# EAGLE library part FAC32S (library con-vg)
CONNECTOR female, 32 pins, block, type D, rows AC, grid 5.08 mm

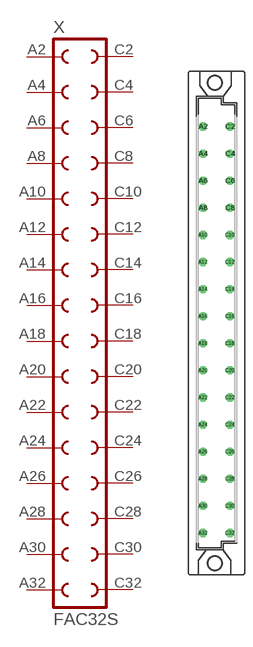
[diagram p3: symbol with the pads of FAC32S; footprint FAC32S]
Designator prefix X

## FAC32S  [FAC32S]
A2  A2  pas
A4  A4  pas
A6  A6  pas
A8  A8  pas
A10  A10  pas
A12  A12  pas
A14  A14  pas
A16  A16  pas
A18  A18  pas
A20  A20  pas
A22  A22  pas
A24  A24  pas
A26  A26  pas
A28  A28  pas
A30  A30  pas
A32  A32  pas
C2  C2  pas
C4  C4  pas
C6  C6  pas
C8  C8  pas
C10  C10  pas
C12  C12  pas
C14  C14  pas
C16  C16  pas
C18  C18  pas
C20  C20  pas
C22  C22  pas
C24  C24  pas
C26  C26  pas
C28  C28  pas
C30  C30  pas
C32  C32  pas

## Footprint FAC32S (pad centres in mm)
CONNECTOR female, 32 pins, type D, rows AC, grid 5.08 mm
drill 1.016 octagon: A2 -2.54,36.83; A4 -2.54,31.75; A6 -2.54,26.67; A8 -2.54,21.59; A10 -2.54,16.51; A12 -2.54,11.43; A14 -2.54,6.35; A16 -2.54,1.27; A18 -2.54,-3.81; A20 -2.54,-8.89; A22 -2.54,-13.97; A24 -2.54,-19.05; A26 -2.54,-24.13; A28 -2.54,-29.21; A30 -2.54,-34.29; A32 -2.54,-39.37; C2 2.54,36.83; C4 2.54,31.75; C6 2.54,26.67; C8 2.54,21.59; C10 2.54,16.51; C12 2.54,11.43; C14 2.54,6.35; C16 2.54,1.27; C18 2.54,-3.81; C20 2.54,-8.89; C22 2.54,-13.97; C24 2.54,-19.05; C26 2.54,-24.13; C28 2.54,-29.21; C30 2.54,-34.29; C32 2.54,-39.37
hole 2.794 at -0.305,45.009
hole 2.794 at -0.305,-45.009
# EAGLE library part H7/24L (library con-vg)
CONNECTOR male, 24 pins + 7 high current pins, block, type H, rows DBZ

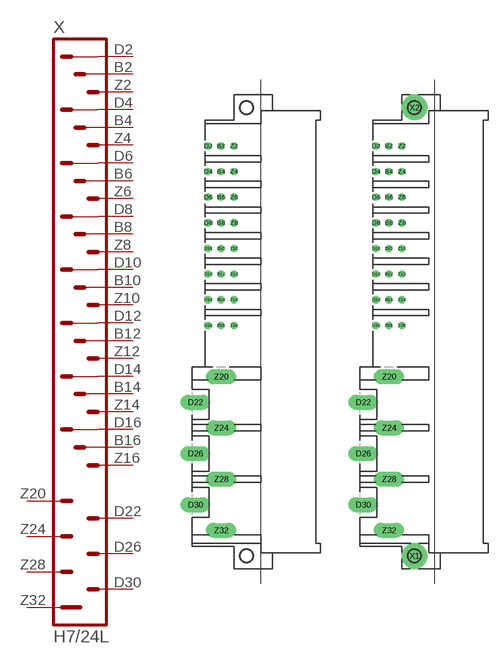
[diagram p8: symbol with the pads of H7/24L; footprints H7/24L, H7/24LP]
Designator prefix X

## H7/24L  [H7/24L]
B2  B2  pas
B4  B4  pas
B6  B6  pas
B8  B8  pas
B10  B10  pas
B12  B12  pas
B14  B14  pas
B16  B16  pas
D2  D2  pas
D4  D4  pas
D6  D6  pas
D8  D8  pas
D10  D10  pas
D12  D12  pas
D14  D14  pas
D16  D16  pas
D22  D22  pas
D26  D26  pas
D30  D30  pas
Z2  Z2  pas
Z4  Z4  pas
Z6  Z6  pas
Z8  Z8  pas
Z10  Z10  pas
Z12  Z12  pas
Z14  Z14  pas
Z16  Z16  pas
Z20  Z20  pas
Z24  Z24  pas
Z28  Z28  pas
Z32  Z32  pas

## H7/24LP  [H7/24LP]
Pads as for H7/24L

## Footprint H7/24L (pad centres in mm)
CONNECTOR male, 24 pins + 7 high current, type H7F24, rows DBZ
drill 0.914 octagon: B2 -5.08,36.83; B4 -5.08,31.75; B6 -5.08,26.67; B8 -5.08,21.59; B10 -5.08,16.51; B12 -5.08,11.43; B14 -5.08,6.35; B16 -5.08,1.27; D2 -7.62,36.83; D4 -7.62,31.75; D6 -7.62,26.67; D8 -7.62,21.59; D10 -7.62,16.51; D12 -7.62,11.43; D14 -7.62,6.35; D16 -7.62,1.27; Z2 -2.54,36.83; Z4 -2.54,31.75; Z6 -2.54,26.67; Z8 -2.54,21.59; Z10 -2.54,16.51; Z12 -2.54,11.43; Z14 -2.54,6.35; Z16 -2.54,1.27
drill 1.6 pad 3 long: D22 -10.16,-13.97; D26 -10.16,-24.13; D30 -10.16,-34.29; Z20 -5.08,-8.89; Z24 -5.08,-19.05; Z28 -5.08,-29.21; Z32 -5.08,-39.37
hole 2.794 at 0,-44.45
hole 2.794 at 0,44.45

## Footprint H7/24LP (pad centres in mm)
CONNECTOR male, 24 pins + 7 high current, type H7F24, rows DBZ with mounting holes
drill 0.914 octagon: B2 -5.08,36.83; B4 -5.08,31.75; B6 -5.08,26.67; B8 -5.08,21.59; B10 -5.08,16.51; B12 -5.08,11.43; B14 -5.08,6.35; B16 -5.08,1.27; D2 -7.62,36.83; D4 -7.62,31.75; D6 -7.62,26.67; D8 -7.62,21.59; D10 -7.62,16.51; D12 -7.62,11.43; D14 -7.62,6.35; D16 -7.62,1.27; Z2 -2.54,36.83; Z4 -2.54,31.75; Z6 -2.54,26.67; Z8 -2.54,21.59; Z10 -2.54,16.51; Z12 -2.54,11.43; Z14 -2.54,6.35; Z16 -2.54,1.27
drill 1.6 pad 3 long: D22 -10.16,-13.97; D26 -10.16,-24.13; D30 -10.16,-34.29; Z20 -5.08,-8.89; Z24 -5.08,-19.05; Z28 -5.08,-29.21; Z32 -5.08,-39.37
drill 2.794 pad 5.08 round: X1 0,-44.45; X2 0,44.45
hole 2.794 at 0,-44.45
hole 2.794 at 0,44.45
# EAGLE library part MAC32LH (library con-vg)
CONNECTOR male, 32 pins, block, type C/2, rows AC, grid 5.08 mm with mounting clip

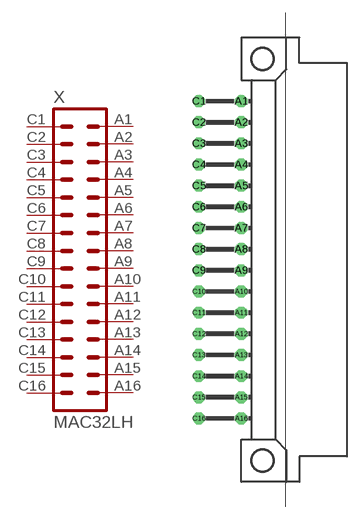
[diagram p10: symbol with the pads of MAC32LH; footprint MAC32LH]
Designator prefix X

## MAC32LH  [MAC32LH]
A1  A1  pas
A2  A2  pas
A3  A3  pas
A4  A4  pas
A5  A5  pas
A6  A6  pas
A7  A7  pas
A8  A8  pas
A9  A9  pas
A10  A10  pas
A11  A11  pas
A12  A12  pas
A13  A13  pas
A14  A14  pas
A15  A15  pas
A16  A16  pas
C1  C1  pas
C2  C2  pas
C3  C3  pas
C4  C4  pas
C5  C5  pas
C6  C6  pas
C7  C7  pas
C8  C8  pas
C9  C9  pas
C10  C10  pas
C11  C11  pas
C12  C12  pas
C13  C13  pas
C14  C14  pas
C15  C15  pas
C16  C16  pas

## Footprint MAC32LH (pad centres in mm)
CONNECTOR male, 32 pins, type C/2, rows AC, grid 5.08 mm with mountig clip
drill 0.914 octagon: A1 -2.54,19.05; A2 -2.54,16.51; A3 -2.54,13.97; A4 -2.54,11.43; A5 -2.54,8.89; A6 -2.54,6.35; A7 -2.54,3.81; A8 -2.54,1.27; A9 -2.54,-1.27; A10 -2.54,-3.81; A11 -2.54,-6.35; A12 -2.54,-8.89; A13 -2.54,-11.43; A14 -2.54,-13.97; A15 -2.54,-16.51; A16 -2.54,-19.05; C1 -7.62,19.05; C2 -7.62,16.51; C3 -7.62,13.97; C4 -7.62,11.43; C5 -7.62,8.89; C6 -7.62,6.35; C7 -7.62,3.81; C8 -7.62,1.27; C9 -7.62,-1.27; C10 -7.62,-3.81; C11 -7.62,-6.35; C12 -7.62,-8.89; C13 -7.62,-11.43; C14 -7.62,-13.97; C15 -7.62,-16.51; C16 -7.62,-19.05
hole 2.794 at 0,-24.13
hole 2.794 at 0,24.13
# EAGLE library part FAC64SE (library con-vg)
CONNECTOR female, 64 pins, single, type C, rows AC, grid 5.08 mm

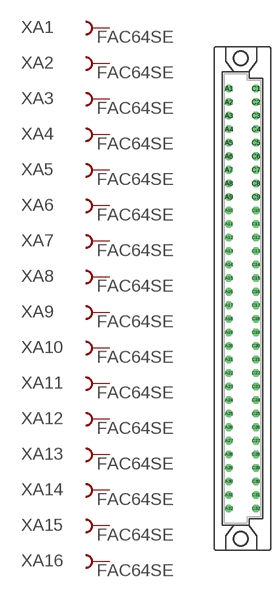
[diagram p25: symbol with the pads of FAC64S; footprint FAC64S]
Designator prefix X; gates A1=F A2=F A3=F A4=F A5=F A6=F A7=F A8=F A9=F A10=F A11=F A12=F A13=F A14=F A15=F A16=F A17=F A18=F A19=F A20=F A21=F A22=F A23=F A24=F A25=F A26=F A27=F A28=F A29=F A30=F A31=F A32=F C1=F C2=F C3=F C4=F C5=F C6=F C7=F C8=F C9=F C10=F C11=F C12=F C13=F C14=F C15=F C16=F C17=F C18=F C19=F C20=F C21=F C22=F C23=F C24=F C25=F C26=F C27=F C28=F C29=F C30=F C31=F C32=F

## FAC64SE  [FAC64S]
A1  A1:B  pas
A2  A2:B  pas
A3  A3:B  pas
A4  A4:B  pas
A5  A5:B  pas
A6  A6:B  pas
A7  A7:B  pas
A8  A8:B  pas
A9  A9:B  pas
A10  A10:B  pas
A11  A11:B  pas
A12  A12:B  pas
A13  A13:B  pas
A14  A14:B  pas
A15  A15:B  pas
A16  A16:B  pas
A17  A17:B  pas
A18  A18:B  pas
A19  A19:B  pas
A20  A20:B  pas
A21  A21:B  pas
A22  A22:B  pas
A23  A23:B  pas
A24  A24:B  pas
A25  A25:B  pas
A26  A26:B  pas
A27  A27:B  pas
A28  A28:B  pas
A29  A29:B  pas
A30  A30:B  pas
A31  A31:B  pas
A32  A32:B  pas
C1  C1:B  pas
C2  C2:B  pas
C3  C3:B  pas
C4  C4:B  pas
C5  C5:B  pas
C6  C6:B  pas
C7  C7:B  pas
C8  C8:B  pas
C9  C9:B  pas
C10  C10:B  pas
C11  C11:B  pas
C12  C12:B  pas
C13  C13:B  pas
C14  C14:B  pas
C15  C15:B  pas
C16  C16:B  pas
C17  C17:B  pas
C18  C18:B  pas
C19  C19:B  pas
C20  C20:B  pas
C21  C21:B  pas
C22  C22:B  pas
C23  C23:B  pas
C24  C24:B  pas
C25  C25:B  pas
C26  C26:B  pas
C27  C27:B  pas
C28  C28:B  pas
C29  C29:B  pas
C30  C30:B  pas
C31  C31:B  pas
C32  C32:B  pas

## Footprint FAC64S (pad centres in mm)
CONNECTOR female, 64 pins, type C, rows AC, grid 5.08 mm
drill 0.914 octagon: A1 -2.54,39.37; A2 -2.54,36.83; A3 -2.54,34.29; A4 -2.54,31.75; A5 -2.54,29.21; A6 -2.54,26.67; A7 -2.54,24.13; A8 -2.54,21.59; A9 -2.54,19.05; A10 -2.54,16.51; A11 -2.54,13.97; A12 -2.54,11.43; A13 -2.54,8.89; A14 -2.54,6.35; A15 -2.54,3.81; A16 -2.54,1.27; A17 -2.54,-1.27; A18 -2.54,-3.81; A19 -2.54,-6.35; A20 -2.54,-8.89; A21 -2.54,-11.43; A22 -2.54,-13.97; A23 -2.54,-16.51; A24 -2.54,-19.05; A25 -2.54,-21.59; A26 -2.54,-24.13; A27 -2.54,-26.67; A28 -2.54,-29.21; A29 -2.54,-31.75; A30 -2.54,-34.29; A31 -2.54,-36.83; A32 -2.54,-39.37; C1 2.54,39.37; C2 2.54,36.83; C3 2.54,34.29; C4 2.54,31.75; C5 2.54,29.21; C6 2.54,26.67; C7 2.54,24.13; C8 2.54,21.59; C9 2.54,19.05; C10 2.54,16.51; C11 2.54,13.97; C12 2.54,11.43; C13 2.54,8.89; C14 2.54,6.35; C15 2.54,3.81; C16 2.54,1.27; C17 2.54,-1.27; C18 2.54,-3.81; C19 2.54,-6.35; C20 2.54,-8.89; C21 2.54,-11.43; C22 2.54,-13.97; C23 2.54,-16.51; C24 2.54,-19.05; C25 2.54,-21.59; C26 2.54,-24.13; C27 2.54,-26.67; C28 2.54,-29.21; C29 2.54,-31.75; C30 2.54,-34.29; C31 2.54,-36.83; C32 2.54,-39.37
hole 2.794 at -0.305,45.009
hole 2.794 at -0.305,-45.009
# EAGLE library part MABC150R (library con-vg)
CONNECTOR male, 150 pins, single, type R, rows ABC, grid 2.54 mm

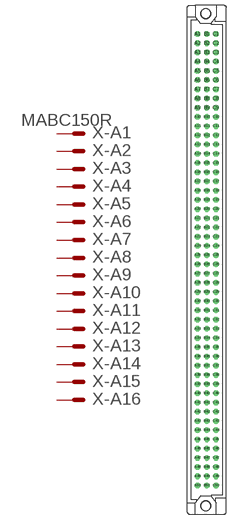
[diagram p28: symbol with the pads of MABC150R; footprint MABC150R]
Designator prefix X; gates -A1=MVAL -A2=MAL -A3=MAL -A4=MAL -A5=MAL -A6=MAL -A7=MAL -A8=MAL -A9=MAL -A10=MAL -A11=MAL -A12=MAL -A13=MAL -A14=MAL -A15=MAL -A16=MAL -A17=MAL -A18=MAL -A19=MAL -A20=MAL -A21=MAL -A22=MAL -A23=MAL -A24=MAL -A25=MAL -A26=MAL -A27=MAL -A28=MAL -A29=MAL -A30=MAL -A31=MAL -A32=MAL -A33=MAL -A34=MAL -A35=MAL -A36=MAL -A37=MAL -A38=MAL -A39=MAL -A40=MAL -A41=MAL -A42=MAL -A43=MAL -A44=MAL -A45=MAL -A46=MAL -A47=MAL -A48=MAL -A49=MAL -A50=MAL -B1=MVAL -B2=MAL -B3=MAL -B4=MAL -B5=MAL -B6=MAL -B7=MAL -B8=MAL -B9=MAL -B10=MAL -B11=MAL -B12=MAL -B13=MAL -B14=MAL -B15=MAL -B16=MAL -B17=MAL -B18=MAL -B19=MAL -B20=MAL -B21=MAL -B22=MAL -B23=MAL -B24=MAL -B25=MAL -B26=MAL -B27=MAL -B28=MAL -B29=MAL -B30=MAL -B31=MAL -B32=MAL -B33=MAL -B34=MAL -B35=MAL -B36=MAL -B37=MAL -B38=MAL -B39=MAL -B40=MAL -B41=MAL -B42=MAL -B43=MAL -B44=MAL -B45=MAL -B46=MAL -B47=MAL -B48=MAL -B49=MAL -B50=MAL -C1=MVAL -C2=MAL -C3=MAL -C4=MAL -C5=MAL -C6=MAL -C7=MAL -C8=MAL -C9=MAL -C10=MAL -C11=MAL -C12=MAL -C13=MAL -C14=MAL -C15=MAL -C16=MAL -C17=MAL -C18=MAL -C19=MAL -C20=MAL -C21=MAL -C22=MAL -C23=MAL -C24=MAL -C25=MAL -C26=MAL -C27=MAL -C28=MAL -C29=MAL -C30=MAL -C31=MAL -C32=MAL -C33=MAL -C34=MAL -C35=MAL -C36=MAL -C37=MAL -C38=MAL -C39=MAL -C40=MAL -C41=MAL -C42=MAL -C43=MAL -C44=MAL -C45=MAL -C46=MAL -C47=MAL -C48=MAL -C49=MAL -C50=MAL

## MABC150R  [MABC150R]
A1  -A1:S  pas
A2  -A2:S  pas
A3  -A3:S  pas
A4  -A4:S  pas
A5  -A5:S  pas
A6  -A6:S  pas
A7  -A7:S  pas
A8  -A8:S  pas
A9  -A9:S  pas
A10  -A10:S  pas
A11  -A11:S  pas
A12  -A12:S  pas
A13  -A13:S  pas
A14  -A14:S  pas
A15  -A15:S  pas
A16  -A16:S  pas
A17  -A17:S  pas
A18  -A18:S  pas
A19  -A19:S  pas
A20  -A20:S  pas
A21  -A21:S  pas
A22  -A22:S  pas
A23  -A23:S  pas
A24  -A24:S  pas
A25  -A25:S  pas
A26  -A26:S  pas
A27  -A27:S  pas
A28  -A28:S  pas
A29  -A29:S  pas
A30  -A30:S  pas
A31  -A31:S  pas
A32  -A32:S  pas
A33  -A33:S  pas
A34  -A34:S  pas
A35  -A35:S  pas
A36  -A36:S  pas
A37  -A37:S  pas
A38  -A38:S  pas
A39  -A39:S  pas
A40  -A40:S  pas
A41  -A41:S  pas
A42  -A42:S  pas
A43  -A43:S  pas
A44  -A44:S  pas
A45  -A45:S  pas
A46  -A46:S  pas
A47  -A47:S  pas
A48  -A48:S  pas
A49  -A49:S  pas
A50  -A50:S  pas
B1  -B1:S  pas
B2  -B2:S  pas
B3  -B3:S  pas
B4  -B4:S  pas
B5  -B5:S  pas
B6  -B6:S  pas
B7  -B7:S  pas
B8  -B8:S  pas
B9  -B9:S  pas
B10  -B10:S  pas
B11  -B11:S  pas
B12  -B12:S  pas
B13  -B13:S  pas
B14  -B14:S  pas
B15  -B15:S  pas
B16  -B16:S  pas
B17  -B17:S  pas
B18  -B18:S  pas
B19  -B19:S  pas
B20  -B20:S  pas
B21  -B21:S  pas
B22  -B22:S  pas
B23  -B23:S  pas
B24  -B24:S  pas
B25  -B25:S  pas
B26  -B26:S  pas
B27  -B27:S  pas
B28  -B28:S  pas
B29  -B29:S  pas
B30  -B30:S  pas
B31  -B31:S  pas
B32  -B32:S  pas
B33  -B33:S  pas
B34  -B34:S  pas
B35  -B35:S  pas
B36  -B36:S  pas
B37  -B37:S  pas
B38  -B38:S  pas
B39  -B39:S  pas
B40  -B40:S  pas
B41  -B41:S  pas
B42  -B42:S  pas
B43  -B43:S  pas
B44  -B44:S  pas
B45  -B45:S  pas
B46  -B46:S  pas
B47  -B47:S  pas
B48  -B48:S  pas
B49  -B49:S  pas
B50  -B50:S  pas
C1  -C1:S  pas
C2  -C2:S  pas
C3  -C3:S  pas
C4  -C4:S  pas
C5  -C5:S  pas
C6  -C6:S  pas
C7  -C7:S  pas
C8  -C8:S  pas
C9  -C9:S  pas
C10  -C10:S  pas
C11  -C11:S  pas
C12  -C12:S  pas
C13  -C13:S  pas
C14  -C14:S  pas
C15  -C15:S  pas
C16  -C16:S  pas
C17  -C17:S  pas
C18  -C18:S  pas
C19  -C19:S  pas
C20  -C20:S  pas
C21  -C21:S  pas
C22  -C22:S  pas
C23  -C23:S  pas
C24  -C24:S  pas
C25  -C25:S  pas
C26  -C26:S  pas
C27  -C27:S  pas
C28  -C28:S  pas
C29  -C29:S  pas
C30  -C30:S  pas
C31  -C31:S  pas
C32  -C32:S  pas
C33  -C33:S  pas
C34  -C34:S  pas
C35  -C35:S  pas
C36  -C36:S  pas
C37  -C37:S  pas
C38  -C38:S  pas
C39  -C39:S  pas
C40  -C40:S  pas
C41  -C41:S  pas
C42  -C42:S  pas
C43  -C43:S  pas
C44  -C44:S  pas
C45  -C45:S  pas
C46  -C46:S  pas
C47  -C47:S  pas
C48  -C48:S  pas
C49  -C49:S  pas
C50  -C50:S  pas

## Footprint MABC150R (pad centres in mm)
CONNECTOR male, 150 pins, type R, rows ABC, grid 2.54 mm
drill 1.016 octagon: A1 -2.54,62.23; A2 -2.54,59.69; A3 -2.54,57.15; A4 -2.54,54.61; A5 -2.54,52.07; A6 -2.54,49.53; A7 -2.54,46.99; A8 -2.54,44.45; A9 -2.54,41.91; A10 -2.54,39.37; A11 -2.54,36.83; A12 -2.54,34.29; A13 -2.54,31.75; A14 -2.54,29.21; A15 -2.54,26.67; A16 -2.54,24.13; A17 -2.54,21.59; A18 -2.54,19.05; A19 -2.54,16.51; A20 -2.54,13.97; A21 -2.54,11.43; A22 -2.54,8.89; A23 -2.54,6.35; A24 -2.54,3.81; A25 -2.54,1.27; A26 -2.54,-1.27; A27 -2.54,-3.81; A28 -2.54,-6.35; A29 -2.54,-8.89; A30 -2.54,-11.43; A31 -2.54,-13.97; A32 -2.54,-16.51; A33 -2.54,-19.05; A34 -2.54,-21.59; A35 -2.54,-24.13; A36 -2.54,-26.67; A37 -2.54,-29.21; A38 -2.54,-31.75; A39 -2.54,-34.29; A40 -2.54,-36.83; A41 -2.54,-39.37; A42 -2.54,-41.91; A43 -2.54,-44.45; A44 -2.54,-46.99; A45 -2.54,-49.53; A46 -2.54,-52.07; A47 -2.54,-54.61; A48 -2.54,-57.15; A49 -2.54,-59.69; A50 -2.54,-62.23; B1 0,62.23; B2 0,59.69; B3 0,57.15; B4 0,54.61; B5 0,52.07; B6 0,49.53; B7 0,46.99; B8 0,44.45; B9 0,41.91; B10 0,39.37; B11 0,36.83; B12 0,34.29; B13 0,31.75; B14 0,29.21; B15 0,26.67; B16 0,24.13; B17 0,21.59; B18 0,19.05; B19 0,16.51; B20 0,13.97; B21 0,11.43; B22 0,8.89; B23 0,6.35; B24 0,3.81; B25 0,1.27; B26 0,-1.27; B27 0,-3.81; B28 0,-6.35; B29 0,-8.89; B30 0,-11.43; B31 0,-13.97; B32 0,-16.51; B33 0,-19.05; B34 0,-21.59; B35 0,-24.13; B36 0,-26.67; B37 0,-29.21; B38 0,-31.75; B39 0,-34.29; B40 0,-36.83; B41 0,-39.37; B42 0,-41.91; B43 0,-44.45; B44 0,-46.99; B45 0,-49.53; B46 0,-52.07; B47 0,-54.61; B48 0,-57.15; B49 0,-59.69; B50 0,-62.23; C1 2.54,62.23; C2 2.54,59.69; C3 2.54,57.15; C4 2.54,54.61; C5 2.54,52.07; C6 2.54,49.53; C7 2.54,46.99; C8 2.54,44.45; C9 2.54,41.91; C10 2.54,39.37; C11 2.54,36.83; C12 2.54,34.29; C13 2.54,31.75; C14 2.54,29.21; C15 2.54,26.67; C16 2.54,24.13; C17 2.54,21.59; C18 2.54,19.05; C19 2.54,16.51; C20 2.54,13.97; C21 2.54,11.43; C22 2.54,8.89; C23 2.54,6.35; C24 2.54,3.81; C25 2.54,1.27; C26 2.54,-1.27; C27 2.54,-3.81; C28 2.54,-6.35; C29 2.54,-8.89; C30 2.54,-11.43; C31 2.54,-13.97; C32 2.54,-16.51; C33 2.54,-19.05; C34 2.54,-21.59; C35 2.54,-24.13; C36 2.54,-26.67; C37 2.54,-29.21; C38 2.54,-31.75; C39 2.54,-34.29; C40 2.54,-36.83; C41 2.54,-39.37; C42 2.54,-41.91; C43 2.54,-44.45; C44 2.54,-46.99; C45 2.54,-49.53; C46 2.54,-52.07; C47 2.54,-54.61; C48 2.54,-57.15; C49 2.54,-59.69; C50 2.54,-62.23
hole 2.794 at -0.305,67.86
hole 2.794 at -0.305,-67.86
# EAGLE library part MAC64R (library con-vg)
CONNECTOR male, 64 pins, single, type R, rows AC, grid 5.08 mm with mounting clip

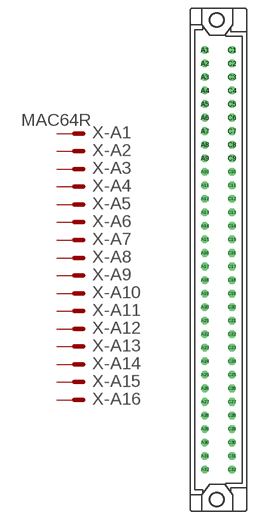
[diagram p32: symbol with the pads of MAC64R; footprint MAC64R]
Designator prefix X; gates -A1=MVAL -A2=MAL -A3=MAL -A4=MAL -A5=MAL -A6=MAL -A7=MAL -A8=MAL -A9=MAL -A10=MAL -A11=MAL -A12=MAL -A13=MAL -A14=MAL -A15=MAL -A16=MAL -A17=MAL -A18=MAL -A19=MAL -A20=MAL -A21=MAL -A22=MAL -A23=MAL -A24=MAL -A25=MAL -A26=MAL -A27=MAL -A28=MAL -A29=MAL -A30=MAL -A31=MAL -A32=MAL -C1=MVAL -C2=MAL -C3=MAL -C4=MAL -C5=MAL -C6=MAL -C7=MAL -C8=MAL -C9=MAL -C10=MAL -C11=MAL -C12=MAL -C13=MAL -C14=MAL -C15=MAL -C16=MAL -C17=MAL -C18=MAL -C19=MAL -C20=MAL -C21=MAL -C22=MAL -C23=MAL -C24=MAL -C25=MAL -C26=MAL -C27=MAL -C28=MAL -C29=MAL -C30=MAL -C31=MAL -C32=MAL

## MAC64R  [MAC64R]
A1  -A1:S  pas
A2  -A2:S  pas
A3  -A3:S  pas
A4  -A4:S  pas
A5  -A5:S  pas
A6  -A6:S  pas
A7  -A7:S  pas
A8  -A8:S  pas
A9  -A9:S  pas
A10  -A10:S  pas
A11  -A11:S  pas
A12  -A12:S  pas
A13  -A13:S  pas
A14  -A14:S  pas
A15  -A15:S  pas
A16  -A16:S  pas
A17  -A17:S  pas
A18  -A18:S  pas
A19  -A19:S  pas
A20  -A20:S  pas
A21  -A21:S  pas
A22  -A22:S  pas
A23  -A23:S  pas
A24  -A24:S  pas
A25  -A25:S  pas
A26  -A26:S  pas
A27  -A27:S  pas
A28  -A28:S  pas
A29  -A29:S  pas
A30  -A30:S  pas
A31  -A31:S  pas
A32  -A32:S  pas
C1  -C1:S  pas
C2  -C2:S  pas
C3  -C3:S  pas
C4  -C4:S  pas
C5  -C5:S  pas
C6  -C6:S  pas
C7  -C7:S  pas
C8  -C8:S  pas
C9  -C9:S  pas
C10  -C10:S  pas
C11  -C11:S  pas
C12  -C12:S  pas
C13  -C13:S  pas
C14  -C14:S  pas
C15  -C15:S  pas
C16  -C16:S  pas
C17  -C17:S  pas
C18  -C18:S  pas
C19  -C19:S  pas
C20  -C20:S  pas
C21  -C21:S  pas
C22  -C22:S  pas
C23  -C23:S  pas
C24  -C24:S  pas
C25  -C25:S  pas
C26  -C26:S  pas
C27  -C27:S  pas
C28  -C28:S  pas
C29  -C29:S  pas
C30  -C30:S  pas
C31  -C31:S  pas
C32  -C32:S  pas

## Footprint MAC64R (pad centres in mm)
CONNECTOR male, 64 pins, type R, rows AC, grid 5.08 mm with mounting clip
drill 0.914 octagon: A1 -2.54,39.37; A2 -2.54,36.83; A3 -2.54,34.29; A4 -2.54,31.75; A5 -2.54,29.21; A6 -2.54,26.67; A7 -2.54,24.13; A8 -2.54,21.59; A9 -2.54,19.05; A10 -2.54,16.51; A11 -2.54,13.97; A12 -2.54,11.43; A13 -2.54,8.89; A14 -2.54,6.35; A15 -2.54,3.81; A16 -2.54,1.27; A17 -2.54,-1.27; A18 -2.54,-3.81; A19 -2.54,-6.35; A20 -2.54,-8.89; A21 -2.54,-11.43; A22 -2.54,-13.97; A23 -2.54,-16.51; A24 -2.54,-19.05; A25 -2.54,-21.59; A26 -2.54,-24.13; A27 -2.54,-26.67; A28 -2.54,-29.21; A29 -2.54,-31.75; A30 -2.54,-34.29; A31 -2.54,-36.83; A32 -2.54,-39.37; C1 2.54,39.37; C2 2.54,36.83; C3 2.54,34.29; C4 2.54,31.75; C5 2.54,29.21; C6 2.54,26.67; C7 2.54,24.13; C8 2.54,21.59; C9 2.54,19.05; C10 2.54,16.51; C11 2.54,13.97; C12 2.54,11.43; C13 2.54,8.89; C14 2.54,6.35; C15 2.54,3.81; C16 2.54,1.27; C17 2.54,-1.27; C18 2.54,-3.81; C19 2.54,-6.35; C20 2.54,-8.89; C21 2.54,-11.43; C22 2.54,-13.97; C23 2.54,-16.51; C24 2.54,-19.05; C25 2.54,-21.59; C26 2.54,-24.13; C27 2.54,-26.67; C28 2.54,-29.21; C29 2.54,-31.75; C30 2.54,-34.29; C31 2.54,-36.83; C32 2.54,-39.37
hole 2.794 at -0.305,45
hole 2.794 at -0.305,-45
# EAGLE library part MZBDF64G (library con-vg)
CONNECTOR male, 64 pins, single, type G, rows DBZ, grid 3.81

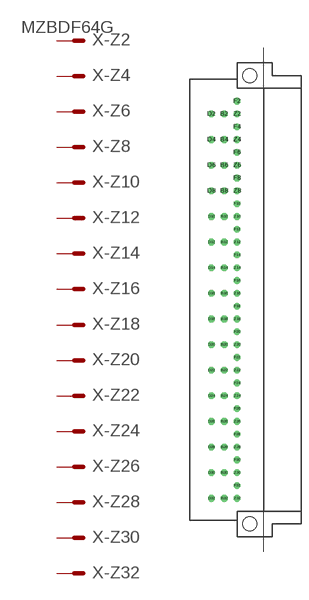
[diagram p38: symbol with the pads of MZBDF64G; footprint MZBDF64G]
Designator prefix X; gates -Z2=MVAL -Z4=MAL -Z6=MAL -Z8=MAL -Z10=MAL -Z12=MAL -Z14=MAL -Z16=MAL -Z18=MAL -Z20=MAL -Z22=MAL -Z24=MAL -Z26=MAL -Z28=MAL -Z30=MAL -Z32=MAL -B2=MVAL -B4=MAL -B6=MAL -B8=MAL -B10=MAL -B12=MAL -B14=MAL -B16=MAL -B18=MAL -B20=MAL -B22=MAL -B24=MAL -B26=MAL -B28=MAL -B30=MAL -B32=MAL -D2=MVAL -D4=MAL -D6=MAL -D8=MAL -D10=MAL -D12=MAL -D14=MAL -D16=MAL -D18=MAL -D20=MAL -D22=MAL -D24=MAL -D26=MAL -D28=MAL -D30=MAL -D32=MAL -F2=MVAL -F4=MAL -F6=MAL -F8=MAL -F10=MAL -F12=MAL -F14=MAL -F16=MAL -F18=MAL -F20=MAL -F22=MAL -F24=MAL -F26=MAL -F28=MAL -F30=MAL -F32=MAL

## MZBDF64G  [MZBDF64G]
B2  -B2:S  pas
B4  -B4:S  pas
B6  -B6:S  pas
B8  -B8:S  pas
B10  -B10:S  pas
B12  -B12:S  pas
B14  -B14:S  pas
B16  -B16:S  pas
B18  -B18:S  pas
B20  -B20:S  pas
B22  -B22:S  pas
B24  -B24:S  pas
B26  -B26:S  pas
B28  -B28:S  pas
B30  -B30:S  pas
B32  -B32:S  pas
D2  -D2:S  pas
D4  -D4:S  pas
D6  -D6:S  pas
D8  -D8:S  pas
D10  -D10:S  pas
D12  -D12:S  pas
D14  -D14:S  pas
D16  -D16:S  pas
D18  -D18:S  pas
D20  -D20:S  pas
D22  -D22:S  pas
D24  -D24:S  pas
D26  -D26:S  pas
D28  -D28:S  pas
D30  -D30:S  pas
D32  -D32:S  pas
F2  -F2:S  pas
F4  -F4:S  pas
F6  -F6:S  pas
F8  -F8:S  pas
F10  -F10:S  pas
F12  -F12:S  pas
F14  -F14:S  pas
F16  -F16:S  pas
F18  -F18:S  pas
F20  -F20:S  pas
F22  -F22:S  pas
F24  -F24:S  pas
F26  -F26:S  pas
F28  -F28:S  pas
F30  -F30:S  pas
F32  -F32:S  pas
Z2  -Z2:S  pas
Z4  -Z4:S  pas
Z6  -Z6:S  pas
Z8  -Z8:S  pas
Z10  -Z10:S  pas
Z12  -Z12:S  pas
Z14  -Z14:S  pas
Z16  -Z16:S  pas
Z18  -Z18:S  pas
Z20  -Z20:S  pas
Z22  -Z22:S  pas
Z24  -Z24:S  pas
Z26  -Z26:S  pas
Z28  -Z28:S  pas
Z30  -Z30:S  pas
Z32  -Z32:S  pas

## Footprint MZBDF64G (pad centres in mm)
CONNECTOR male, 64 pins, type G, rows DBZ, grid 2.54
drill 0.813 octagon: B2 -5.08,36.83; B4 -5.08,31.75; B6 -5.08,26.67; B8 -5.08,21.59; B10 -5.08,16.51; B12 -5.08,11.43; B14 -5.08,6.35; B16 -5.08,1.27; B18 -5.08,-3.81; B20 -5.08,-8.89; B22 -5.08,-13.97; B24 -5.08,-19.05; B26 -5.08,-24.13; B28 -5.08,-29.21; B30 -5.08,-34.29; B32 -5.08,-39.37; D2 -7.62,36.83; D4 -7.62,31.75; D6 -7.62,26.67; D8 -7.62,21.59; D10 -7.62,16.51; D12 -7.62,11.43; D14 -7.62,6.35; D16 -7.62,1.27; D18 -7.62,-3.81; D20 -7.62,-8.89; D22 -7.62,-13.97; D24 -7.62,-19.05; D26 -7.62,-24.13; D28 -7.62,-29.21; D30 -7.62,-34.29; D32 -7.62,-39.37; F2 -2.54,39.37; F4 -2.54,34.29; F6 -2.54,29.21; F8 -2.54,24.13; F10 -2.54,19.05; F12 -2.54,13.97; F14 -2.54,8.89; F16 -2.54,3.81; F18 -2.54,-1.27; F20 -2.54,-6.35; F22 -2.54,-11.43; F24 -2.54,-16.51; F26 -2.54,-21.59; F28 -2.54,-26.67; F30 -2.54,-31.75; F32 -2.54,-36.83; Z2 -2.54,36.83; Z4 -2.54,31.75; Z6 -2.54,26.67; Z8 -2.54,21.59; Z10 -2.54,16.51; Z12 -2.54,11.43; Z14 -2.54,6.35; Z16 -2.54,1.27; Z18 -2.54,-3.81; Z20 -2.54,-8.89; Z22 -2.54,-13.97; Z24 -2.54,-19.05; Z26 -2.54,-24.13; Z28 -2.54,-29.21; Z30 -2.54,-34.29; Z32 -2.54,-39.37
hole 2.794 at 0,44.45
hole 2.794 at 0,-44.45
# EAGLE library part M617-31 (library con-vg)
CONNECTOR male, 31 pins, single, DIN41617

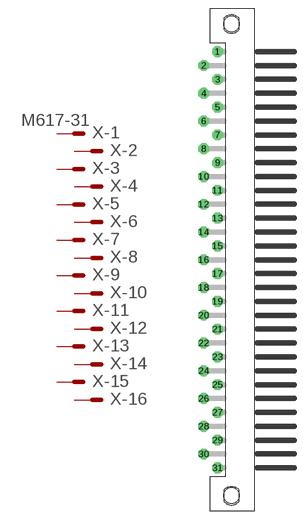
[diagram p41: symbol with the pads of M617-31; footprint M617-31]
Designator prefix X; gates -1=MVAL -2=MAL -3=MAL -4=MAL -5=MAL -6=MAL -7=MAL -8=MAL -9=MAL -10=MAL -11=MAL -12=MAL -13=MAL -14=MAL -15=MAL -16=MAL -17=MAL -18=MAL -19=MAL -20=MAL -21=MAL -22=MAL -23=MAL -24=MAL -25=MAL -26=MAL -27=MAL -28=MAL -29=MAL -30=MAL -31=MAL

## M617-31  [M617-31]
1  -1:S  pas
2  -2:S  pas
3  -3:S  pas
4  -4:S  pas
5  -5:S  pas
6  -6:S  pas
7  -7:S  pas
8  -8:S  pas
9  -9:S  pas
10  -10:S  pas
11  -11:S  pas
12  -12:S  pas
13  -13:S  pas
14  -14:S  pas
15  -15:S  pas
16  -16:S  pas
17  -17:S  pas
18  -18:S  pas
19  -19:S  pas
20  -20:S  pas
21  -21:S  pas
22  -22:S  pas
23  -23:S  pas
24  -24:S  pas
25  -25:S  pas
26  -26:S  pas
27  -27:S  pas
28  -28:S  pas
29  -29:S  pas
30  -30:S  pas
31  -31:S  pas

## Footprint M617-31 (pad centres in mm)
CONNECTOR male, 31 pins, DIN41617
drill 1.3 octagon: 1 -4,35; 2 -6.5,32.5; 3 -4,30; 4 -6.5,27.5; 5 -4,25; 6 -6.5,22.5; 7 -4,20; 8 -6.5,17.5; 9 -4,15; 10 -6.5,12.5; 11 -4,10; 12 -6.5,7.5; 13 -4,5; 14 -6.5,2.5; 15 -4,0; 16 -6.5,-2.5; 17 -4,-5; 18 -6.5,-7.5; 19 -4,-10; 20 -6.5,-12.5; 21 -4,-15; 22 -6.5,-17.5; 23 -4,-20; 24 -6.5,-22.5; 25 -4,-25; 26 -6.5,-27.5; 27 -4,-30; 28 -6.5,-32.5; 29 -4,-35; 30 -6.5,-37.5; 31 -4,-40
hole 2.8 at -1.5,-45
hole 2.8 at -1.5,40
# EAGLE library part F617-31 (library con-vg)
CONNECTOR female, DIN 41617, 31 pins, single

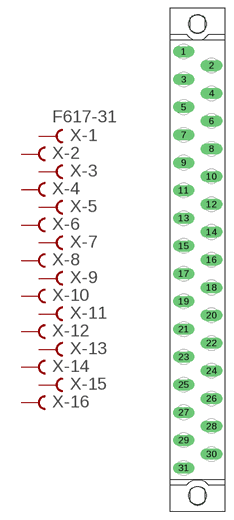
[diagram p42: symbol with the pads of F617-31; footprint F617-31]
Designator prefix X; gates -1=FVAL -2=FEM -3=FEM -4=FEM -5=FEM -6=FEM -7=FEM -8=FEM -9=FEM -10=FEM -11=FEM -12=FEM -13=FEM -14=FEM -15=FEM -16=FEM -17=FEM -18=FEM -19=FEM -20=FEM -21=FEM -22=FEM -23=FEM -24=FEM -25=FEM -26=FEM -27=FEM -28=FEM -29=FEM -30=FEM -31=FEM

## F617-31  [F617-31]
1  -1:B  pas
2  -2:B  pas
3  -3:B  pas
4  -4:B  pas
5  -5:B  pas
6  -6:B  pas
7  -7:B  pas
8  -8:B  pas
9  -9:B  pas
10  -10:B  pas
11  -11:B  pas
12  -12:B  pas
13  -13:B  pas
14  -14:B  pas
15  -15:B  pas
16  -16:B  pas
17  -17:B  pas
18  -18:B  pas
19  -19:B  pas
20  -20:B  pas
21  -21:B  pas
22  -22:B  pas
23  -23:B  pas
24  -24:B  pas
25  -25:B  pas
26  -26:B  pas
27  -27:B  pas
28  -28:B  pas
29  -29:B  pas
30  -30:B  pas
31  -31:B  pas

## Footprint F617-31 (pad centres in mm)
CONNECTOR female, 31 pins, DIN 41617
drill 1.3 long: 1 -2.5,37.5; 2 2.5,35; 3 -2.5,32.5; 4 2.5,30; 5 -2.5,27.5; 6 2.5,25; 7 -2.5,22.5; 8 2.5,20; 9 -2.5,17.5; 10 2.5,15; 11 -2.5,12.5; 12 2.5,10; 13 -2.5,7.5; 14 2.5,5; 15 -2.5,2.5; 16 2.5,0; 17 -2.5,-2.5; 18 2.5,-5; 19 -2.5,-7.5; 20 2.5,-10; 21 -2.5,-12.5; 22 2.5,-15; 23 -2.5,-17.5; 24 2.5,-20; 25 -2.5,-22.5; 26 2.5,-25; 27 -2.5,-27.5; 28 2.5,-30; 29 -2.5,-32.5; 30 2.5,-35; 31 -2.5,-37.5
hole 3.2 at 0,-42.5
hole 3.2 at 0,42.5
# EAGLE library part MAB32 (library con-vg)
CONNECTOR male, 32 pins, type B, row A, grid 2.54 mm

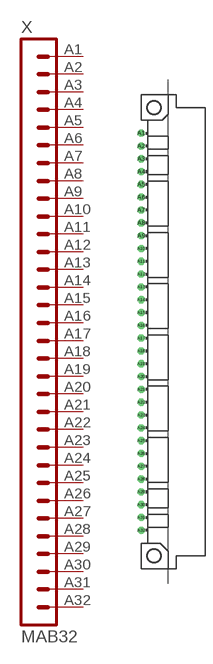
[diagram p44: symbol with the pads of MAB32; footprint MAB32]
Designator prefix X

## MAB32  [MAB32]
A1  1  pas
A2  2  pas
A3  3  pas
A4  4  pas
A5  5  pas
A6  6  pas
A7  7  pas
A8  8  pas
A9  9  pas
A10  10  pas
A11  11  pas
A12  12  pas
A13  13  pas
A14  14  pas
A15  15  pas
A16  16  pas
A17  17  pas
A18  18  pas
A19  19  pas
A20  20  pas
A21  21  pas
A22  22  pas
A23  23  pas
A24  24  pas
A25  25  pas
A26  26  pas
A27  27  pas
A28  28  pas
A29  29  pas
A30  30  pas
A31  31  pas
A32  32  pas

## Footprint MAB32 (pad centres in mm)
CONNECTOR male, 32 pins, type B, rows A, grid 2.54 mm
drill 0.914 octagon: A1 -2.54,39.37; A2 -2.54,36.83; A3 -2.54,34.29; A4 -2.54,31.75; A5 -2.54,29.21; A6 -2.54,26.67; A7 -2.54,24.13; A8 -2.54,21.59; A9 -2.54,19.05; A10 -2.54,16.51; A11 -2.54,13.97; A12 -2.54,11.43; A13 -2.54,8.89; A14 -2.54,6.35; A15 -2.54,3.81; A16 -2.54,1.27; A17 -2.54,-1.27; A18 -2.54,-3.81; A19 -2.54,-6.35; A20 -2.54,-8.89; A21 -2.54,-11.43; A22 -2.54,-13.97; A23 -2.54,-16.51; A24 -2.54,-19.05; A25 -2.54,-21.59; A26 -2.54,-24.13; A27 -2.54,-26.67; A28 -2.54,-29.21; A29 -2.54,-31.75; A30 -2.54,-34.29; A31 -2.54,-36.83; A32 -2.54,-39.37
hole 2.794 at 0,44.45
hole 2.794 at 0,-44.45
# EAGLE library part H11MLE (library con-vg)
CONNECTOR male, 11 high current pins, block, type H

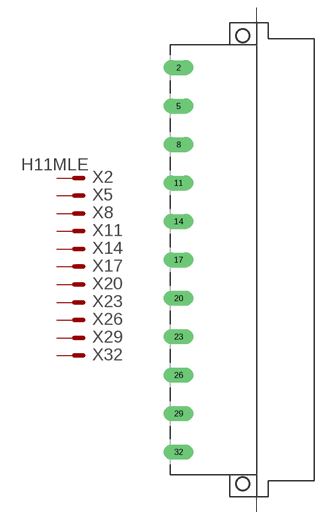
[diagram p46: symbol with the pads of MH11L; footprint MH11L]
Designator prefix X; gates 2=MVAL 5=MAL 8=MAL 11=MAL 14=MAL 17=MAL 20=MAL 23=MAL 26=MAL 29=MAL 32=MAL

## H11MLE  [MH11L]
2  2:S  pas
5  5:S  pas
8  8:S  pas
11  11:S  pas
14  14:S  pas
17  17:S  pas
20  20:S  pas
23  23:S  pas
26  26:S  pas
29  29:S  pas
32  32:S  pas

## Footprint MH11L (pad centres in mm)
CONNECTOR male, 11 pins, type H
drill 1.676 pad 3 long: 2 -12.7,38.1; 5 -12.7,30.48; 8 -12.7,22.86; 11 -12.7,15.24; 14 -12.7,7.62; 17 -12.7,0; 20 -12.7,-7.62; 23 -12.7,-15.24; 26 -12.7,-22.86; 29 -12.7,-30.48; 32 -12.7,-38.1
hole 2.794 at 0,-44.45
hole 2.794 at 0,44.45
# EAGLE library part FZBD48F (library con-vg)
CONNECTOR female, 48 pins, type F, rows ABZ, grid 5.08 mm

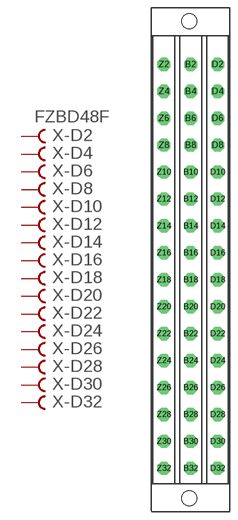
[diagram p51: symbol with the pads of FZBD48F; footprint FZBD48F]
Designator prefix X; gates -D2=FVAL -D4=FEM -D6=FEM -D8=FEM -D10=FEM -D12=FEM -D14=FEM -D16=FEM -D18=FEM -D20=FEM -D22=FEM -D24=FEM -D26=FEM -D28=FEM -D30=FEM -D32=FEM -B2=FVAL -B4=FEM -B6=FEM -B8=FEM -B10=FEM -B12=FEM -B14=FEM -B16=FEM -B18=FEM -B20=FEM -B22=FEM -B24=FEM -B26=FEM -B28=FEM -B30=FEM -B32=FEM -Z2=FVAL -Z4=FEM -Z6=FEM -Z8=FEM -Z10=FEM -Z12=FEM -Z14=FEM -Z16=FEM -Z18=FEM -Z20=FEM -Z22=FEM -Z24=FEM -Z26=FEM -Z28=FEM -Z30=FEM -Z32=FEM

## FZBD48F  [FZBD48F]
B2  -B2:B  pas
B4  -B4:B  pas
B6  -B6:B  pas
B8  -B8:B  pas
B10  -B10:B  pas
B12  -B12:B  pas
B14  -B14:B  pas
B16  -B16:B  pas
B18  -B18:B  pas
B20  -B20:B  pas
B22  -B22:B  pas
B24  -B24:B  pas
B26  -B26:B  pas
B28  -B28:B  pas
B30  -B30:B  pas
B32  -B32:B  pas
D2  -D2:B  pas
D4  -D4:B  pas
D6  -D6:B  pas
D8  -D8:B  pas
D10  -D10:B  pas
D12  -D12:B  pas
D14  -D14:B  pas
D16  -D16:B  pas
D18  -D18:B  pas
D20  -D20:B  pas
D22  -D22:B  pas
D24  -D24:B  pas
D26  -D26:B  pas
D28  -D28:B  pas
D30  -D30:B  pas
D32  -D32:B  pas
Z2  -Z2:B  pas
Z4  -Z4:B  pas
Z6  -Z6:B  pas
Z8  -Z8:B  pas
Z10  -Z10:B  pas
Z12  -Z12:B  pas
Z14  -Z14:B  pas
Z16  -Z16:B  pas
Z18  -Z18:B  pas
Z20  -Z20:B  pas
Z22  -Z22:B  pas
Z24  -Z24:B  pas
Z26  -Z26:B  pas
Z28  -Z28:B  pas
Z30  -Z30:B  pas
Z32  -Z32:B  pas

## Footprint FZBD48F (pad centres in mm)
CONNECTOR female, 48 pins, type F, rows ABZ, grid 5.08 mm
drill 1.676 octagon: B2 0,36.855; B4 0,31.775; B6 0,26.695; B8 0,21.615; B10 0,16.535; B12 0,11.455; B14 0,6.375; B16 0,1.295; B18 0,-3.785; B20 0,-8.865; B22 0,-13.945; B24 0,-19.025; B26 0,-24.105; B28 0,-29.185; B30 0,-34.265; B32 0,-39.345; D2 5.08,36.855; D4 5.08,31.775; D6 5.08,26.695; D8 5.08,21.615; D10 5.08,16.535; D12 5.08,11.455; D14 5.08,6.375; D16 5.08,1.295; D18 5.08,-3.785; D20 5.08,-8.865; D22 5.08,-13.945; D24 5.08,-19.025; D26 5.08,-24.105; D28 5.08,-29.185; D30 5.08,-34.265; D32 5.08,-39.345; Z2 -5.08,36.855; Z4 -5.08,31.775; Z6 -5.08,26.695; Z8 -5.08,21.615; Z10 -5.08,16.535; Z12 -5.08,11.455; Z14 -5.08,6.375; Z16 -5.08,1.295; Z18 -5.08,-3.785; Z20 -5.08,-8.865; Z22 -5.08,-13.945; Z24 -5.08,-19.025; Z26 -5.08,-24.105; Z28 -5.08,-29.185; Z30 -5.08,-34.265; Z32 -5.08,-39.345
hole 2.794 at -0.305,44.983
hole 2.794 at -0.305,-44.983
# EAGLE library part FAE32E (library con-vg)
CONNECTOR femlae 32 pins, type E, rows AC, grid 5.08 mm

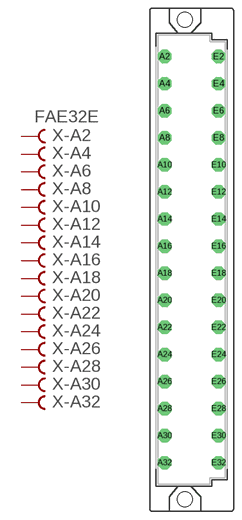
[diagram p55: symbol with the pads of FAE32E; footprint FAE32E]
Designator prefix X; gates -A2=FVAL -A4=FEM -A6=FEM -A8=FEM -A10=FEM -A12=FEM -A14=FEM -A16=FEM -A18=FEM -A20=FEM -A22=FEM -A24=FEM -A26=FEM -A28=FEM -A30=FEM -A32=FEM -E2=FVAL -E4=FEM -E6=FEM -E8=FEM -E10=FEM -E12=FEM -E14=FEM -E16=FEM -E18=FEM -E20=FEM -E22=FEM -E24=FEM -E26=FEM -E28=FEM -E30=FEM -E32=FEM

## FAE32E  [FAE32E]
A2  -A2:B  pas
A4  -A4:B  pas
A6  -A6:B  pas
A8  -A8:B  pas
A10  -A10:B  pas
A12  -A12:B  pas
A14  -A14:B  pas
A16  -A16:B  pas
A18  -A18:B  pas
A20  -A20:B  pas
A22  -A22:B  pas
A24  -A24:B  pas
A26  -A26:B  pas
A28  -A28:B  pas
A30  -A30:B  pas
A32  -A32:B  pas
E2  -E2:B  pas
E4  -E4:B  pas
E6  -E6:B  pas
E8  -E8:B  pas
E10  -E10:B  pas
E12  -E12:B  pas
E14  -E14:B  pas
E16  -E16:B  pas
E18  -E18:B  pas
E20  -E20:B  pas
E22  -E22:B  pas
E24  -E24:B  pas
E26  -E26:B  pas
E28  -E28:B  pas
E30  -E30:B  pas
E32  -E32:B  pas

## Footprint FAE32E (pad centres in mm)
CONNECTOR femlae 32 pins, type E, rows AC, grid 5.08 mm
drill 1.676 octagon: A2 -5.08,38.1; A4 -5.08,33.02; A6 -5.08,27.94; A8 -5.08,22.86; A10 -5.08,17.78; A12 -5.08,12.7; A14 -5.08,7.62; A16 -5.08,2.54; A18 -5.08,-2.54; A20 -5.08,-7.62; A22 -5.08,-12.7; A24 -5.08,-17.78; A26 -5.08,-22.86; A28 -5.08,-27.94; A30 -5.08,-33.02; A32 -5.08,-38.1; E2 5.08,38.1; E4 5.08,33.02; E6 5.08,27.94; E8 5.08,22.86; E10 5.08,17.78; E12 5.08,12.7; E14 5.08,7.62; E16 5.08,2.54; E18 5.08,-2.54; E20 5.08,-7.62; E22 5.08,-12.7; E24 5.08,-17.78; E26 5.08,-22.86; E28 5.08,-27.94; E30 5.08,-33.02; E32 5.08,-38.1
hole 2.794 at -1.27,44.983
hole 2.794 at -1.27,-44.983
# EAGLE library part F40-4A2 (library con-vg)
CONNECTOR female, 40 pins + 4 high current, type C

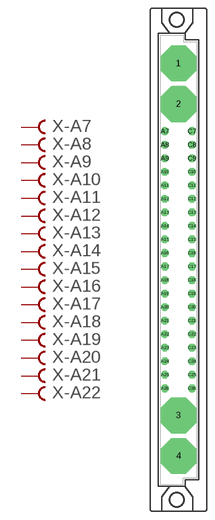
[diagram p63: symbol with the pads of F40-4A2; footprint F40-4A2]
Designator prefix X; gates -A7=FEM -A8=FEM -A9=FEM -A10=FEM -A11=FEM -A12=FEM -A13=FEM -A14=FEM -A15=FEM -A16=FEM -A17=FEM -A18=FEM -A19=FEM -A20=FEM -A21=FEM -A22=FEM -A23=FEM -A24=FEM -A25=FEM -A26=FEM -C7=FEM -C8=FEM -C9=FEM -C10=FEM -C11=FEM -C12=FEM -C13=FEM -C14=FEM -C15=FEM -C16=FEM -C17=FEM -C18=FEM -C19=FEM -C20=FEM -C21=FEM -C22=FEM -C23=FEM -C24=FEM -C25=FEM -C26=FEM -1=FEM-HIGHCUR -2=FEM-HIGHCUR -3=FEM-HIGHCUR -4=FEM-HIGHCUR

## F40-4A2  [F40-4A2]
1  -1:B  pas
2  -2:B  pas
3  -3:B  pas
4  -4:B  pas
A7  -A7:B  pas
A8  -A8:B  pas
A9  -A9:B  pas
A10  -A10:B  pas
A11  -A11:B  pas
A12  -A12:B  pas
A13  -A13:B  pas
A14  -A14:B  pas
A15  -A15:B  pas
A16  -A16:B  pas
A17  -A17:B  pas
A18  -A18:B  pas
A19  -A19:B  pas
A20  -A20:B  pas
A21  -A21:B  pas
A22  -A22:B  pas
A23  -A23:B  pas
A24  -A24:B  pas
A25  -A25:B  pas
A26  -A26:B  pas
C7  -C7:B  pas
C8  -C8:B  pas
C9  -C9:B  pas
C10  -C10:B  pas
C11  -C11:B  pas
C12  -C12:B  pas
C13  -C13:B  pas
C14  -C14:B  pas
C15  -C15:B  pas
C16  -C16:B  pas
C17  -C17:B  pas
C18  -C18:B  pas
C19  -C19:B  pas
C20  -C20:B  pas
C21  -C21:B  pas
C22  -C22:B  pas
C23  -C23:B  pas
C24  -C24:B  pas
C25  -C25:B  pas
C26  -C26:B  pas

## Footprint F40-4A2 (pad centres in mm)
CONNECTOR female, 40 pins + 4 high current, type C
drill 5.7 octagon: 1 0,36.83; 2 0,29.21; 3 0,-29.21; 4 0,-36.83
drill 0.914 octagon: A7 -2.54,24.13; A8 -2.54,21.59; A9 -2.54,19.05; A10 -2.54,16.51; A11 -2.54,13.97; A12 -2.54,11.43; A13 -2.54,8.89; A14 -2.54,6.35; A15 -2.54,3.81; A16 -2.54,1.27; A17 -2.54,-1.27; A18 -2.54,-3.81; A19 -2.54,-6.35; A20 -2.54,-8.89; A21 -2.54,-11.43; A22 -2.54,-13.97; A23 -2.54,-16.51; A24 -2.54,-19.05; A25 -2.54,-21.59; A26 -2.54,-24.13; C7 2.54,24.13; C8 2.54,21.59; C9 2.54,19.05; C10 2.54,16.51; C11 2.54,13.97; C12 2.54,11.43; C13 2.54,8.89; C14 2.54,6.35; C15 2.54,3.81; C16 2.54,1.27; C17 2.54,-1.27; C18 2.54,-3.81; C19 2.54,-6.35; C20 2.54,-8.89; C21 2.54,-11.43; C22 2.54,-13.97; C23 2.54,-16.51; C24 2.54,-19.05; C25 2.54,-21.59; C26 2.54,-24.13
hole 2.794 at -0.305,45.009
hole 2.794 at -0.305,-45.009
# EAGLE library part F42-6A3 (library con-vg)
CONNECTOR female, 42 pins + 6 high current, type C

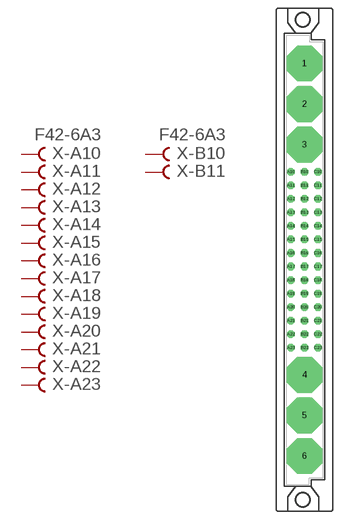
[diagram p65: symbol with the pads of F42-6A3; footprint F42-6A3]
Designator prefix X; gates -A10=FVAL -A11=FEM -A12=FEM -A13=FEM -A14=FEM -A15=FEM -A16=FEM -A17=FEM -A18=FEM -A19=FEM -A20=FEM -A21=FEM -A22=FEM -A23=FEM -B10=FVAL -B11=FEM -B12=FEM -B13=FEM -B14=FEM -B15=FEM -B16=FEM -B17=FEM -B18=FEM -B19=FEM -B20=FEM -B21=FEM -B22=FEM -B23=FEM -C10=FVAL -C11=FEM -C12=FEM -C13=FEM -C14=FEM -C15=FEM -C16=FEM -C17=FEM -C18=FEM -C19=FEM -C20=FEM -C21=FEM -C22=FEM -C23=FEM -1=FEM-HIGHCUR -2=FEM-HIGHCUR -3=FEM-HIGHCUR -4=FEM-HIGHCUR -5=FEM-HIGHCUR -6=FEM-HIGHCUR

## F42-6A3  [F42-6A3]
1  -1:B  pas
2  -2:B  pas
3  -3:B  pas
4  -4:B  pas
5  -5:B  pas
6  -6:B  pas
A10  -A10:B  pas
A11  -A11:B  pas
A12  -A12:B  pas
A13  -A13:B  pas
A14  -A14:B  pas
A15  -A15:B  pas
A16  -A16:B  pas
A17  -A17:B  pas
A18  -A18:B  pas
A19  -A19:B  pas
A20  -A20:B  pas
A21  -A21:B  pas
A22  -A22:B  pas
A23  -A23:B  pas
B10  -B10:B  pas
B11  -B11:B  pas
B12  -B12:B  pas
B13  -B13:B  pas
B14  -B14:B  pas
B15  -B15:B  pas
B16  -B16:B  pas
B17  -B17:B  pas
B18  -B18:B  pas
B19  -B19:B  pas
B20  -B20:B  pas
B21  -B21:B  pas
B22  -B22:B  pas
B23  -B23:B  pas
C10  -C10:B  pas
C11  -C11:B  pas
C12  -C12:B  pas
C13  -C13:B  pas
C14  -C14:B  pas
C15  -C15:B  pas
C16  -C16:B  pas
C17  -C17:B  pas
C18  -C18:B  pas
C19  -C19:B  pas
C20  -C20:B  pas
C21  -C21:B  pas
C22  -C22:B  pas
C23  -C23:B  pas

## Footprint F42-6A3 (pad centres in mm)
CONNECTOR female, 42 pins + 6 high current, type C
drill 5.7 octagon: 1 0,36.83; 2 0,29.21; 3 0,21.59; 4 0,-21.59; 5 0,-29.21; 6 0,-36.83
drill 0.914 octagon: A10 -2.54,16.51; A11 -2.54,13.97; A12 -2.54,11.43; A13 -2.54,8.89; A14 -2.54,6.35; A15 -2.54,3.81; A16 -2.54,1.27; A17 -2.54,-1.27; A18 -2.54,-3.81; A19 -2.54,-6.35; A20 -2.54,-8.89; A21 -2.54,-11.43; A22 -2.54,-13.97; A23 -2.54,-16.51; B10 0,16.51; B11 0,13.97; B12 0,11.43; B13 0,8.89; B14 0,6.35; B15 0,3.81; B16 0,1.27; B17 0,-1.27; B18 0,-3.81; B19 0,-6.35; B20 0,-8.89; B21 0,-11.43; B22 0,-13.97; B23 0,-16.51; C10 2.54,16.51; C11 2.54,13.97; C12 2.54,11.43; C13 2.54,8.89; C14 2.54,6.35; C15 2.54,3.81; C16 2.54,1.27; C17 2.54,-1.27; C18 2.54,-3.81; C19 2.54,-6.35; C20 2.54,-8.89; C21 2.54,-11.43; C22 2.54,-13.97; C23 2.54,-16.51
hole 2.794 at -0.305,45.009
hole 2.794 at -0.305,-45.009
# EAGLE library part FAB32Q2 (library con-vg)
CONNECTOR female, 32 pins, type Q/2, rows AB, grid 2.54 mm

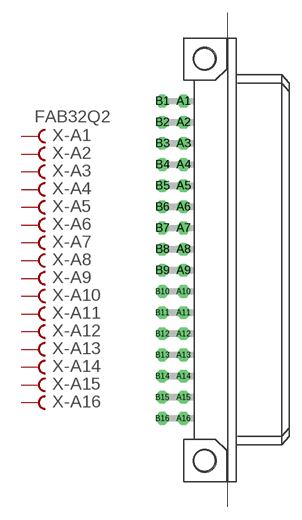
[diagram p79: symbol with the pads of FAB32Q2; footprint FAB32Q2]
Designator prefix X; gates -A1=FVAL -A2=FEM -A3=FEM -A4=FEM -A5=FEM -A6=FEM -A7=FEM -A8=FEM -A9=FEM -A10=FEM -A11=FEM -A12=FEM -A13=FEM -A14=FEM -A15=FEM -A16=FEM -B1=FVAL -B2=FEM -B3=FEM -B4=FEM -B5=FEM -B6=FEM -B7=FEM -B8=FEM -B9=FEM -B10=FEM -B11=FEM -B12=FEM -B13=FEM -B14=FEM -B15=FEM -B16=FEM

## FAB32Q2  [FAB32Q2]
A1  -A1:B  pas
A2  -A2:B  pas
A3  -A3:B  pas
A4  -A4:B  pas
A5  -A5:B  pas
A6  -A6:B  pas
A7  -A7:B  pas
A8  -A8:B  pas
A9  -A9:B  pas
A10  -A10:B  pas
A11  -A11:B  pas
A12  -A12:B  pas
A13  -A13:B  pas
A14  -A14:B  pas
A15  -A15:B  pas
A16  -A16:B  pas
B1  -B1:B  pas
B2  -B2:B  pas
B3  -B3:B  pas
B4  -B4:B  pas
B5  -B5:B  pas
B6  -B6:B  pas
B7  -B7:B  pas
B8  -B8:B  pas
B9  -B9:B  pas
B10  -B10:B  pas
B11  -B11:B  pas
B12  -B12:B  pas
B13  -B13:B  pas
B14  -B14:B  pas
B15  -B15:B  pas
B16  -B16:B  pas

## Footprint FAB32Q2 (pad centres in mm)
CONNECTOR female, 32 pins, type Q/2, rows AB, grid 2.54 mm
drill 1.016 octagon: A1 -2.54,19.05; A2 -2.54,16.51; A3 -2.54,13.97; A4 -2.54,11.43; A5 -2.54,8.89; A6 -2.54,6.35; A7 -2.54,3.81; A8 -2.54,1.27; A9 -2.54,-1.27; A10 -2.54,-3.81; A11 -2.54,-6.35; A12 -2.54,-8.89; A13 -2.54,-11.43; A14 -2.54,-13.97; A15 -2.54,-16.51; A16 -2.54,-19.05; B1 -5.08,19.05; B2 -5.08,16.51; B3 -5.08,13.97; B4 -5.08,11.43; B5 -5.08,8.89; B6 -5.08,6.35; B7 -5.08,3.81; B8 -5.08,1.27; B9 -5.08,-1.27; B10 -5.08,-3.81; B11 -5.08,-6.35; B12 -5.08,-8.89; B13 -5.08,-11.43; B14 -5.08,-13.97; B15 -5.08,-16.51; B16 -5.08,-19.05
hole 2.794 at 0,-24.136
hole 2.794 at 0,24.136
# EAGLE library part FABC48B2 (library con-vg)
CONNECTOR female, 48 pins, type C/2, rows ABC, grid 2.54 mm

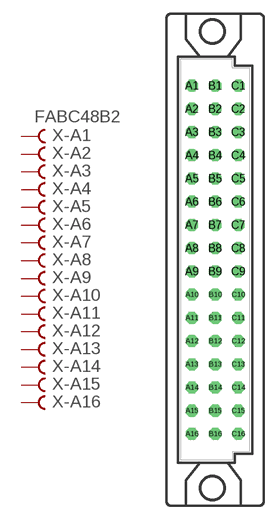
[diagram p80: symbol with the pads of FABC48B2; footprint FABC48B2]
Designator prefix X; gates -A1=FVAL -A2=FEM -A3=FEM -A4=FEM -A5=FEM -A6=FEM -A7=FEM -A8=FEM -A9=FEM -A10=FEM -A11=FEM -A12=FEM -A13=FEM -A14=FEM -A15=FEM -A16=FEM -B1=FVAL -B2=FEM -B3=FEM -B4=FEM -B5=FEM -B6=FEM -B7=FEM -B8=FEM -B9=FEM -B10=FEM -B11=FEM -B12=FEM -B13=FEM -B14=FEM -B15=FEM -B16=FEM -C1=FVAL -C2=FEM -C3=FEM -C4=FEM -C5=FEM -C6=FEM -C7=FEM -C8=FEM -C9=FEM -C10=FEM -C11=FEM -C12=FEM -C13=FEM -C14=FEM -C15=FEM -C16=FEM

## FABC48B2  [FABC48B2]
A1  -A1:B  pas
A2  -A2:B  pas
A3  -A3:B  pas
A4  -A4:B  pas
A5  -A5:B  pas
A6  -A6:B  pas
A7  -A7:B  pas
A8  -A8:B  pas
A9  -A9:B  pas
A10  -A10:B  pas
A11  -A11:B  pas
A12  -A12:B  pas
A13  -A13:B  pas
A14  -A14:B  pas
A15  -A15:B  pas
A16  -A16:B  pas
B1  -B1:B  pas
B2  -B2:B  pas
B3  -B3:B  pas
B4  -B4:B  pas
B5  -B5:B  pas
B6  -B6:B  pas
B7  -B7:B  pas
B8  -B8:B  pas
B9  -B9:B  pas
B10  -B10:B  pas
B11  -B11:B  pas
B12  -B12:B  pas
B13  -B13:B  pas
B14  -B14:B  pas
B15  -B15:B  pas
B16  -B16:B  pas
C1  -C1:B  pas
C2  -C2:B  pas
C3  -C3:B  pas
C4  -C4:B  pas
C5  -C5:B  pas
C6  -C6:B  pas
C7  -C7:B  pas
C8  -C8:B  pas
C9  -C9:B  pas
C10  -C10:B  pas
C11  -C11:B  pas
C12  -C12:B  pas
C13  -C13:B  pas
C14  -C14:B  pas
C15  -C15:B  pas
C16  -C16:B  pas

## Footprint FABC48B2 (pad centres in mm)
CONNECTOR female, 48 pins, type C/2, rows ABC, grid 2.54 mm
drill 0.813 octagon: A1 -1.27,19.05; A2 -1.27,16.51; A3 -1.27,13.97; A4 -1.27,11.43; A5 -1.27,8.89; A6 -1.27,6.35; A7 -1.27,3.81; A8 -1.27,1.27; A9 -1.27,-1.27; A10 -1.27,-3.81; A11 -1.27,-6.35; A12 -1.27,-8.89; A13 -1.27,-11.43; A14 -1.27,-13.97; A15 -1.27,-16.51; A16 -1.27,-19.05; B1 1.27,19.05; B2 1.27,16.51; B3 1.27,13.97; B4 1.27,11.43; B5 1.27,8.89; B6 1.27,6.35; B7 1.27,3.81; B8 1.27,1.27; B9 1.27,-1.27; B10 1.27,-3.81; B11 1.27,-6.35; B12 1.27,-8.89; B13 1.27,-11.43; B14 1.27,-13.97; B15 1.27,-16.51; B16 1.27,-19.05; C1 3.81,19.05; C2 3.81,16.51; C3 3.81,13.97; C4 3.81,11.43; C5 3.81,8.89; C6 3.81,6.35; C7 3.81,3.81; C8 3.81,1.27; C9 3.81,-1.27; C10 3.81,-3.81; C11 3.81,-6.35; C12 3.81,-8.89; C13 3.81,-11.43; C14 3.81,-13.97; C15 3.81,-16.51; C16 3.81,-19.05
hole 2.794 at 0.965,-25
hole 2.794 at 0.965,25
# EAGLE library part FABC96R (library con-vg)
CONNECTOR female, 96 pins, type R, rows ABC, grid 2.54 mm

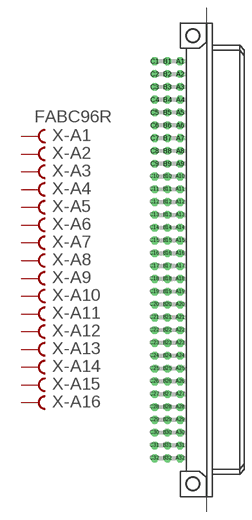
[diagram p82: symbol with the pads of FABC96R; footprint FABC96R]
Designator prefix X; gates -A1=FVAL -A2=FEM -A3=FEM -A4=FEM -A5=FEM -A6=FEM -A7=FEM -A8=FEM -A9=FEM -A10=FEM -A11=FEM -A12=FEM -A13=FEM -A14=FEM -A15=FEM -A16=FEM -A17=FEM -A18=FEM -A19=FEM -A20=FEM -A21=FEM -A22=FEM -A23=FEM -A24=FEM -A25=FEM -A26=FEM -A27=FEM -A28=FEM -A29=FEM -A30=FEM -A31=FEM -A32=FEM -B1=FVAL -B2=FEM -B3=FEM -B4=FEM -B5=FEM -B6=FEM -B7=FEM -B8=FEM -B9=FEM -B10=FEM -B11=FEM -B12=FEM -B13=FEM -B14=FEM -B15=FEM -B16=FEM -B17=FEM -B18=FEM -B19=FEM -B20=FEM -B21=FEM -B22=FEM -B23=FEM -B24=FEM -B25=FEM -B26=FEM -B27=FEM -B28=FEM -B29=FEM -B30=FEM -B31=FEM -B32=FEM -C1=FVAL -C2=FEM -C3=FEM -C4=FEM -C5=FEM -C6=FEM -C7=FEM -C8=FEM -C9=FEM -C10=FEM -C11=FEM -C12=FEM -C13=FEM -C14=FEM -C15=FEM -C16=FEM -C17=FEM -C18=FEM -C19=FEM -C20=FEM -C21=FEM -C22=FEM -C23=FEM -C24=FEM -C25=FEM -C26=FEM -C27=FEM -C28=FEM -C29=FEM -C30=FEM -C31=FEM -C32=FEM

## FABC96R  [FABC96R]
A1  -A1:B  pas
A2  -A2:B  pas
A3  -A3:B  pas
A4  -A4:B  pas
A5  -A5:B  pas
A6  -A6:B  pas
A7  -A7:B  pas
A8  -A8:B  pas
A9  -A9:B  pas
A10  -A10:B  pas
A11  -A11:B  pas
A12  -A12:B  pas
A13  -A13:B  pas
A14  -A14:B  pas
A15  -A15:B  pas
A16  -A16:B  pas
A17  -A17:B  pas
A18  -A18:B  pas
A19  -A19:B  pas
A20  -A20:B  pas
A21  -A21:B  pas
A22  -A22:B  pas
A23  -A23:B  pas
A24  -A24:B  pas
A25  -A25:B  pas
A26  -A26:B  pas
A27  -A27:B  pas
A28  -A28:B  pas
A29  -A29:B  pas
A30  -A30:B  pas
A31  -A31:B  pas
A32  -A32:B  pas
B1  -B1:B  pas
B2  -B2:B  pas
B3  -B3:B  pas
B4  -B4:B  pas
B5  -B5:B  pas
B6  -B6:B  pas
B7  -B7:B  pas
B8  -B8:B  pas
B9  -B9:B  pas
B10  -B10:B  pas
B11  -B11:B  pas
B12  -B12:B  pas
B13  -B13:B  pas
B14  -B14:B  pas
B15  -B15:B  pas
B16  -B16:B  pas
B17  -B17:B  pas
B18  -B18:B  pas
B19  -B19:B  pas
B20  -B20:B  pas
B21  -B21:B  pas
B22  -B22:B  pas
B23  -B23:B  pas
B24  -B24:B  pas
B25  -B25:B  pas
B26  -B26:B  pas
B27  -B27:B  pas
B28  -B28:B  pas
B29  -B29:B  pas
B30  -B30:B  pas
B31  -B31:B  pas
B32  -B32:B  pas
C1  -C1:B  pas
C2  -C2:B  pas
C3  -C3:B  pas
C4  -C4:B  pas
C5  -C5:B  pas
C6  -C6:B  pas
C7  -C7:B  pas
C8  -C8:B  pas
C9  -C9:B  pas
C10  -C10:B  pas
C11  -C11:B  pas
C12  -C12:B  pas
C13  -C13:B  pas
C14  -C14:B  pas
C15  -C15:B  pas
C16  -C16:B  pas
C17  -C17:B  pas
C18  -C18:B  pas
C19  -C19:B  pas
C20  -C20:B  pas
C21  -C21:B  pas
C22  -C22:B  pas
C23  -C23:B  pas
C24  -C24:B  pas
C25  -C25:B  pas
C26  -C26:B  pas
C27  -C27:B  pas
C28  -C28:B  pas
C29  -C29:B  pas
C30  -C30:B  pas
C31  -C31:B  pas
C32  -C32:B  pas

## Footprint FABC96R (pad centres in mm)
CONNECTOR female, 96 pins, type R, rows ABC, grid 2.54 mm
drill 1.016 octagon: A1 -2.54,39.37; A2 -2.54,36.83; A3 -2.54,34.29; A4 -2.54,31.75; A5 -2.54,29.21; A6 -2.54,26.67; A7 -2.54,24.13; A8 -2.54,21.59; A9 -2.54,19.05; A10 -2.54,16.51; A11 -2.54,13.97; A12 -2.54,11.43; A13 -2.54,8.89; A14 -2.54,6.35; A15 -2.54,3.81; A16 -2.54,1.27; A17 -2.54,-1.27; A18 -2.54,-3.81; A19 -2.54,-6.35; A20 -2.54,-8.89; A21 -2.54,-11.43; A22 -2.54,-13.97; A23 -2.54,-16.51; A24 -2.54,-19.05; A25 -2.54,-21.59; A26 -2.54,-24.13; A27 -2.54,-26.67; A28 -2.54,-29.21; A29 -2.54,-31.75; A30 -2.54,-34.29; A31 -2.54,-36.83; A32 -2.54,-39.37; B1 -5.08,39.37; B2 -5.08,36.83; B3 -5.08,34.29; B4 -5.08,31.75; B5 -5.08,29.21; B6 -5.08,26.67; B7 -5.08,24.13; B8 -5.08,21.59; B9 -5.08,19.05; B10 -5.08,16.51; B11 -5.08,13.97; B12 -5.08,11.43; B13 -5.08,8.89; B14 -5.08,6.35; B15 -5.08,3.81; B16 -5.08,1.27; B17 -5.08,-1.27; B18 -5.08,-3.81; B19 -5.08,-6.35; B20 -5.08,-8.89; B21 -5.08,-11.43; B22 -5.08,-13.97; B23 -5.08,-16.51; B24 -5.08,-19.05; B25 -5.08,-21.59; B26 -5.08,-24.13; B27 -5.08,-26.67; B28 -5.08,-29.21; B29 -5.08,-31.75; B30 -5.08,-34.29; B31 -5.08,-36.83; B32 -5.08,-39.37; C1 -7.62,39.37; C2 -7.62,36.83; C3 -7.62,34.29; C4 -7.62,31.75; C5 -7.62,29.21; C6 -7.62,26.67; C7 -7.62,24.13; C8 -7.62,21.59; C9 -7.62,19.05; C10 -7.62,16.51; C11 -7.62,13.97; C12 -7.62,11.43; C13 -7.62,8.89; C14 -7.62,6.35; C15 -7.62,3.81; C16 -7.62,1.27; C17 -7.62,-1.27; C18 -7.62,-3.81; C19 -7.62,-6.35; C20 -7.62,-8.89; C21 -7.62,-11.43; C22 -7.62,-13.97; C23 -7.62,-16.51; C24 -7.62,-19.05; C25 -7.62,-21.59; C26 -7.62,-24.13; C27 -7.62,-26.67; C28 -7.62,-29.21; C29 -7.62,-31.75; C30 -7.62,-34.29; C31 -7.62,-36.83; C32 -7.62,-39.37
hole 2.794 at 0,-44.456
hole 2.794 at 0,44.456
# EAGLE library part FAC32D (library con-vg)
CONNECTOR female, 32 pins, type D, rows AC, grid 5.08 mm

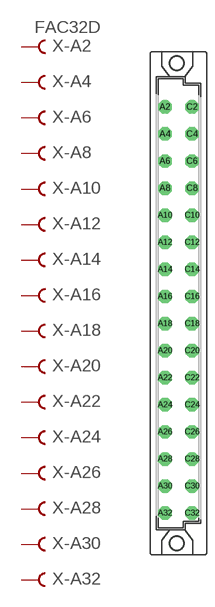
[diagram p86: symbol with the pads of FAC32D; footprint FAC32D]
Designator prefix X; gates -A4=FEM -A6=FEM -A8=FEM -A10=FEM -A12=FEM -A14=FEM -A16=FEM -A18=FEM -A20=FEM -A22=FEM -A24=FEM -A26=FEM -A28=FEM -A30=FEM -A32=FEM -A2=FVAL -C2=FVAL -C4=FEM -C6=FEM -C8=FEM -C10=FEM -C12=FEM -C14=FEM -C16=FEM -C18=FEM -C20=FEM -C22=FEM -C24=FEM -C26=FEM -C28=FEM -C30=FEM -C32=FEM

## FAC32D  [FAC32D]
A2  -A2:B  pas
A4  -A4:B  pas
A6  -A6:B  pas
A8  -A8:B  pas
A10  -A10:B  pas
A12  -A12:B  pas
A14  -A14:B  pas
A16  -A16:B  pas
A18  -A18:B  pas
A20  -A20:B  pas
A22  -A22:B  pas
A24  -A24:B  pas
A26  -A26:B  pas
A28  -A28:B  pas
A30  -A30:B  pas
A32  -A32:B  pas
C2  -C2:B  pas
C4  -C4:B  pas
C6  -C6:B  pas
C8  -C8:B  pas
C10  -C10:B  pas
C12  -C12:B  pas
C14  -C14:B  pas
C16  -C16:B  pas
C18  -C18:B  pas
C20  -C20:B  pas
C22  -C22:B  pas
C24  -C24:B  pas
C26  -C26:B  pas
C28  -C28:B  pas
C30  -C30:B  pas
C32  -C32:B  pas

## Footprint FAC32D (pad centres in mm)
CONNECTOR female, 32 pins, type D, rows AC, grid 5.08 mm
drill 1.676 octagon: A2 -2.54,36.83; A4 -2.54,31.75; A6 -2.54,26.67; A8 -2.54,21.59; A10 -2.54,16.51; A12 -2.54,11.43; A14 -2.54,6.35; A16 -2.54,1.27; A18 -2.54,-3.81; A20 -2.54,-8.89; A22 -2.54,-13.97; A24 -2.54,-19.05; A26 -2.54,-24.13; A28 -2.54,-29.21; A30 -2.54,-34.29; A32 -2.54,-39.37; C2 2.54,36.83; C4 2.54,31.75; C6 2.54,26.67; C8 2.54,21.59; C10 2.54,16.51; C12 2.54,11.43; C14 2.54,6.35; C16 2.54,1.27; C18 2.54,-3.81; C20 2.54,-8.89; C22 2.54,-13.97; C24 2.54,-19.05; C26 2.54,-24.13; C28 2.54,-29.21; C30 2.54,-34.29; C32 2.54,-39.37
hole 2.794 at -0.305,45.009
hole 2.794 at -0.305,-45.009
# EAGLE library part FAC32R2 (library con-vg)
CONNECTOR female, 32 pins, type R/2, rows AC, grid 5.08 mm

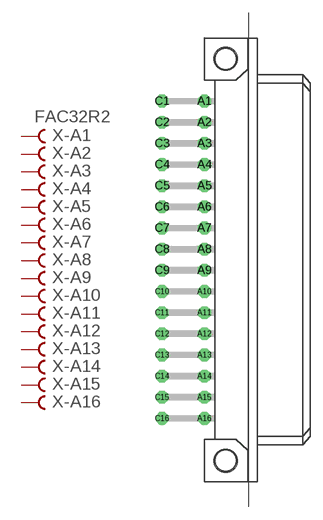
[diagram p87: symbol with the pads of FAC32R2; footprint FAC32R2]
Designator prefix X; gates -A1=FVAL -A2=FEM -A3=FEM -A4=FEM -A5=FEM -A6=FEM -A7=FEM -A8=FEM -A9=FEM -A10=FEM -A11=FEM -A12=FEM -A13=FEM -A14=FEM -A15=FEM -A16=FEM -C1=FVAL -C2=FEM -C3=FEM -C4=FEM -C5=FEM -C6=FEM -C7=FEM -C8=FEM -C9=FEM -C10=FEM -C11=FEM -C12=FEM -C13=FEM -C14=FEM -C15=FEM -C16=FEM

## FAC32R2  [FAC32R2]
A1  -A1:B  pas
A2  -A2:B  pas
A3  -A3:B  pas
A4  -A4:B  pas
A5  -A5:B  pas
A6  -A6:B  pas
A7  -A7:B  pas
A8  -A8:B  pas
A9  -A9:B  pas
A10  -A10:B  pas
A11  -A11:B  pas
A12  -A12:B  pas
A13  -A13:B  pas
A14  -A14:B  pas
A15  -A15:B  pas
A16  -A16:B  pas
C1  -C1:B  pas
C2  -C2:B  pas
C3  -C3:B  pas
C4  -C4:B  pas
C5  -C5:B  pas
C6  -C6:B  pas
C7  -C7:B  pas
C8  -C8:B  pas
C9  -C9:B  pas
C10  -C10:B  pas
C11  -C11:B  pas
C12  -C12:B  pas
C13  -C13:B  pas
C14  -C14:B  pas
C15  -C15:B  pas
C16  -C16:B  pas

## Footprint FAC32R2 (pad centres in mm)
CONNECTOR female, 32 pins, type R/2, rows AC, grid 5.08 mm
drill 1.016 octagon: A1 -2.54,19.05; A2 -2.54,16.51; A3 -2.54,13.97; A4 -2.54,11.43; A5 -2.54,8.89; A6 -2.54,6.35; A7 -2.54,3.81; A8 -2.54,1.27; A9 -2.54,-1.27; A10 -2.54,-3.81; A11 -2.54,-6.35; A12 -2.54,-8.89; A13 -2.54,-11.43; A14 -2.54,-13.97; A15 -2.54,-16.51; A16 -2.54,-19.05; C1 -7.62,19.05; C2 -7.62,16.51; C3 -7.62,13.97; C4 -7.62,11.43; C5 -7.62,8.89; C6 -7.62,6.35; C7 -7.62,3.81; C8 -7.62,1.27; C9 -7.62,-1.27; C10 -7.62,-3.81; C11 -7.62,-6.35; C12 -7.62,-8.89; C13 -7.62,-11.43; C14 -7.62,-13.97; C15 -7.62,-16.51; C16 -7.62,-19.05
hole 2.794 at 0,-24.136
hole 2.794 at 0,24.136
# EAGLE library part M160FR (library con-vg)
CONNECTOR male, 160 pins, type R, rows ABCDE, grid 2.54 mm

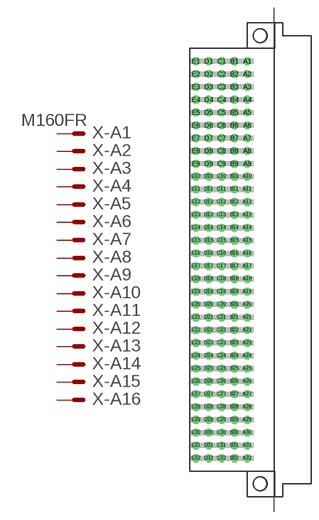
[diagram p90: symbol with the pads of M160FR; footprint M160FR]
Designator prefix X; gates -A1=MVAL -A2=MAL -A3=MAL -A4=MAL -A5=MAL -A6=MAL -A7=MAL -A8=MAL -A9=MAL -A10=MAL -A11=MAL -A12=MAL -A13=MAL -A14=MAL -A15=MAL -A16=MAL -A17=MAL -A18=MAL -A19=MAL -A20=MAL -A21=MAL -A22=MAL -A23=MAL -A24=MAL -A25=MAL -A26=MAL -A27=MAL -A28=MAL -A29=MAL -A30=MAL -A31=MAL -A32=MAL -B1=MVAL -B2=MAL -B3=MAL -B4=MAL -B5=MAL -B6=MAL -B7=MAL -B8=MAL -B9=MAL -B10=MAL -B11=MAL -B12=MAL -B13=MAL -B14=MAL -B15=MAL -B16=MAL -B17=MAL -B18=MAL -B19=MAL -B20=MAL -B21=MAL -B22=MAL -B23=MAL -B24=MAL -B25=MAL -B26=MAL -B27=MAL -B28=MAL -B29=MAL -B30=MAL -B31=MAL -B32=MAL -C1=MVAL -C2=MAL -C3=MAL -C4=MAL -C5=MAL -C6=MAL -C7=MAL -C8=MAL -C9=MAL -C10=MAL -C11=MAL -C12=MAL -C13=MAL -C14=MAL -C15=MAL -C16=MAL -C17=MAL -C18=MAL -C19=MAL -C20=MAL -C21=MAL -C22=MAL -C23=MAL -C24=MAL -C25=MAL -C26=MAL -C27=MAL -C28=MAL -C29=MAL -C30=MAL -C31=MAL -C32=MAL -D1=MVAL -D2=MAL -D3=MAL -D4=MAL -D5=MAL -D6=MAL -D7=MAL -D8=MAL -D9=MAL -D10=MAL -D11=MAL -D12=MAL -D13=MAL -D14=MAL -D15=MAL -D16=MAL -D17=MAL -D18=MAL -D19=MAL -D20=MAL -D21=MAL -D22=MAL -D23=MAL -D24=MAL -D25=MAL -D26=MAL -D27=MAL -D28=MAL -D29=MAL -D30=MAL -D31=MAL -D32=MAL -E1=MVAL -E2=MAL -E3=MAL -E4=MAL -E5=MAL -E6=MAL -E7=MAL -E8=MAL -E9=MAL -E10=MAL -E11=MAL -E12=MAL -E13=MAL -E14=MAL -E15=MAL -E16=MAL -E17=MAL -E18=MAL -E19=MAL -E20=MAL -E21=MAL -E22=MAL -E23=MAL -E24=MAL -E25=MAL -E26=MAL -E27=MAL -E28=MAL -E29=MAL -E30=MAL -E31=MAL -E32=MAL

## M160FR  [M160FR]
A1  -A1:S  pas
A2  -A2:S  pas
A3  -A3:S  pas
A4  -A4:S  pas
A5  -A5:S  pas
A6  -A6:S  pas
A7  -A7:S  pas
A8  -A8:S  pas
A9  -A9:S  pas
A10  -A10:S  pas
A11  -A11:S  pas
A12  -A12:S  pas
A13  -A13:S  pas
A14  -A14:S  pas
A15  -A15:S  pas
A16  -A16:S  pas
A17  -A17:S  pas
A18  -A18:S  pas
A19  -A19:S  pas
A20  -A20:S  pas
A21  -A21:S  pas
A22  -A22:S  pas
A23  -A23:S  pas
A24  -A24:S  pas
A25  -A25:S  pas
A26  -A26:S  pas
A27  -A27:S  pas
A28  -A28:S  pas
A29  -A29:S  pas
A30  -A30:S  pas
A31  -A31:S  pas
A32  -A32:S  pas
B1  -B1:S  pas
B2  -B2:S  pas
B3  -B3:S  pas
B4  -B4:S  pas
B5  -B5:S  pas
B6  -B6:S  pas
B7  -B7:S  pas
B8  -B8:S  pas
B9  -B9:S  pas
B10  -B10:S  pas
B11  -B11:S  pas
B12  -B12:S  pas
B13  -B13:S  pas
B14  -B14:S  pas
B15  -B15:S  pas
B16  -B16:S  pas
B17  -B17:S  pas
B18  -B18:S  pas
B19  -B19:S  pas
B20  -B20:S  pas
B21  -B21:S  pas
B22  -B22:S  pas
B23  -B23:S  pas
B24  -B24:S  pas
B25  -B25:S  pas
B26  -B26:S  pas
B27  -B27:S  pas
B28  -B28:S  pas
B29  -B29:S  pas
B30  -B30:S  pas
B31  -B31:S  pas
B32  -B32:S  pas
C1  -C1:S  pas
C2  -C2:S  pas
C3  -C3:S  pas
C4  -C4:S  pas
C5  -C5:S  pas
C6  -C6:S  pas
C7  -C7:S  pas
C8  -C8:S  pas
C9  -C9:S  pas
C10  -C10:S  pas
C11  -C11:S  pas
C12  -C12:S  pas
C13  -C13:S  pas
C14  -C14:S  pas
C15  -C15:S  pas
C16  -C16:S  pas
C17  -C17:S  pas
C18  -C18:S  pas
C19  -C19:S  pas
C20  -C20:S  pas
C21  -C21:S  pas
C22  -C22:S  pas
C23  -C23:S  pas
C24  -C24:S  pas
C25  -C25:S  pas
C26  -C26:S  pas
C27  -C27:S  pas
C28  -C28:S  pas
C29  -C29:S  pas
C30  -C30:S  pas
C31  -C31:S  pas
C32  -C32:S  pas
D1  -D1:S  pas
D2  -D2:S  pas
D3  -D3:S  pas
D4  -D4:S  pas
D5  -D5:S  pas
D6  -D6:S  pas
D7  -D7:S  pas
D8  -D8:S  pas
D9  -D9:S  pas
D10  -D10:S  pas
D11  -D11:S  pas
D12  -D12:S  pas
D13  -D13:S  pas
D14  -D14:S  pas
D15  -D15:S  pas
D16  -D16:S  pas
D17  -D17:S  pas
D18  -D18:S  pas
D19  -D19:S  pas
D20  -D20:S  pas
D21  -D21:S  pas
D22  -D22:S  pas
D23  -D23:S  pas
D24  -D24:S  pas
D25  -D25:S  pas
D26  -D26:S  pas
D27  -D27:S  pas
D28  -D28:S  pas
D29  -D29:S  pas
D30  -D30:S  pas
D31  -D31:S  pas
D32  -D32:S  pas
E1  -E1:S  pas
E2  -E2:S  pas
E3  -E3:S  pas
E4  -E4:S  pas
E5  -E5:S  pas
E6  -E6:S  pas
E7  -E7:S  pas
E8  -E8:S  pas
E9  -E9:S  pas
E10  -E10:S  pas
E11  -E11:S  pas
E12  -E12:S  pas
E13  -E13:S  pas
E14  -E14:S  pas
E15  -E15:S  pas
E16  -E16:S  pas
E17  -E17:S  pas
E18  -E18:S  pas
E19  -E19:S  pas
E20  -E20:S  pas
E21  -E21:S  pas
E22  -E22:S  pas
E23  -E23:S  pas
E24  -E24:S  pas
E25  -E25:S  pas
E26  -E26:S  pas
E27  -E27:S  pas
E28  -E28:S  pas
E29  -E29:S  pas
E30  -E30:S  pas
E31  -E31:S  pas
E32  -E32:S  pas

## Footprint M160FR (pad centres in mm)
CONNECTOR male, 160 pins, type R, rows ABCDE, grid 2.54 mm
drill 1.016 octagon: A1 -2.54,39.37; A2 -2.54,36.83; A3 -2.54,34.29; A4 -2.54,31.75; A5 -2.54,29.21; A6 -2.54,26.67; A7 -2.54,24.13; A8 -2.54,21.59; A9 -2.54,19.05; A10 -2.54,16.51; A11 -2.54,13.97; A12 -2.54,11.43; A13 -2.54,8.89; A14 -2.54,6.35; A15 -2.54,3.81; A16 -2.54,1.27; A17 -2.54,-1.27; A18 -2.54,-3.81; A19 -2.54,-6.35; A20 -2.54,-8.89; A21 -2.54,-11.43; A22 -2.54,-13.97; A23 -2.54,-16.51; A24 -2.54,-19.05; A25 -2.54,-21.59; A26 -2.54,-24.13; A27 -2.54,-26.67; A28 -2.54,-29.21; A29 -2.54,-31.75; A30 -2.54,-34.29; A31 -2.54,-36.83; A32 -2.54,-39.37; B1 -5.08,39.37; B2 -5.08,36.83; B3 -5.08,34.29; B4 -5.08,31.75; B5 -5.08,29.21; B6 -5.08,26.67; B7 -5.08,24.13; B8 -5.08,21.59; B9 -5.08,19.05; B10 -5.08,16.51; B11 -5.08,13.97; B12 -5.08,11.43; B13 -5.08,8.89; B14 -5.08,6.35; B15 -5.08,3.81; B16 -5.08,1.27; B17 -5.08,-1.27; B18 -5.08,-3.81; B19 -5.08,-6.35; B20 -5.08,-8.89; B21 -5.08,-11.43; B22 -5.08,-13.97; B23 -5.08,-16.51; B24 -5.08,-19.05; B25 -5.08,-21.59; B26 -5.08,-24.13; B27 -5.08,-26.67; B28 -5.08,-29.21; B29 -5.08,-31.75; B30 -5.08,-34.29; B31 -5.08,-36.83; B32 -5.08,-39.37; C1 -7.62,39.37; C2 -7.62,36.83; C3 -7.62,34.29; C4 -7.62,31.75; C5 -7.62,29.21; C6 -7.62,26.67; C7 -7.62,24.13; C8 -7.62,21.59; C9 -7.62,19.05; C10 -7.62,16.51; C11 -7.62,13.97; C12 -7.62,11.43; C13 -7.62,8.89; C14 -7.62,6.35; C15 -7.62,3.81; C16 -7.62,1.27; C17 -7.62,-1.27; C18 -7.62,-3.81; C19 -7.62,-6.35; C20 -7.62,-8.89; C21 -7.62,-11.43; C22 -7.62,-13.97; C23 -7.62,-16.51; C24 -7.62,-19.05; C25 -7.62,-21.59; C26 -7.62,-24.13; C27 -7.62,-26.67; C28 -7.62,-29.21; C29 -7.62,-31.75; C30 -7.62,-34.29; C31 -7.62,-36.83; C32 -7.62,-39.37; D1 -10.16,39.37; D2 -10.16,36.83; D3 -10.16,34.29; D4 -10.16,31.75; D5 -10.16,29.21; D6 -10.16,26.67; D7 -10.16,24.13; D8 -10.16,21.59; D9 -10.16,19.05; D10 -10.16,16.51; D11 -10.16,13.97; D12 -10.16,11.43; D13 -10.16,8.89; D14 -10.16,6.35; D15 -10.16,3.81; D16 -10.16,1.27; D17 -10.16,-1.27; D18 -10.16,-3.81; D19 -10.16,-6.35; D20 -10.16,-8.89; D21 -10.16,-11.43; D22 -10.16,-13.97; D23 -10.16,-16.51; D24 -10.16,-19.05; D25 -10.16,-21.59; D26 -10.16,-24.13; D27 -10.16,-26.67; D28 -10.16,-29.21; D29 -10.16,-31.75; D30 -10.16,-34.29; D31 -10.16,-36.83; D32 -10.16,-39.37; E1 -12.7,39.37; E2 -12.7,36.83; E3 -12.7,34.29; E4 -12.7,31.75; E5 -12.7,29.21; E6 -12.7,26.67; E7 -12.7,24.13; E8 -12.7,21.59; E9 -12.7,19.05; E10 -12.7,16.51; E11 -12.7,13.97; E12 -12.7,11.43; E13 -12.7,8.89; E14 -12.7,6.35; E15 -12.7,3.81; E16 -12.7,1.27; E17 -12.7,-1.27; E18 -12.7,-3.81; E19 -12.7,-6.35; E20 -12.7,-8.89; E21 -12.7,-11.43; E22 -12.7,-13.97; E23 -12.7,-16.51; E24 -12.7,-19.05; E25 -12.7,-21.59; E26 -12.7,-24.13; E27 -12.7,-26.67; E28 -12.7,-29.21; E29 -12.7,-31.75; E30 -12.7,-34.29; E31 -12.7,-36.83; E32 -12.7,-39.37
hole 2.794 at 0,44.45
hole 2.794 at 0,-44.45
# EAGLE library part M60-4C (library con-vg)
CONNECTOR male, 60 pins + 4 coax type C, rows ABC, grid 2.54 mm

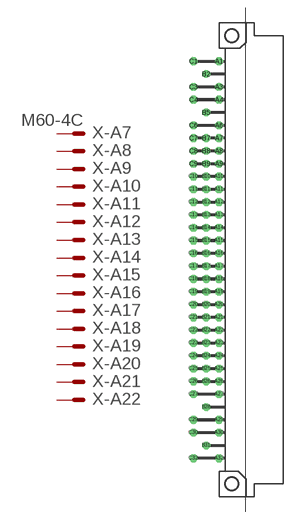
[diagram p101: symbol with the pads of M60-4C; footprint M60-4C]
Designator prefix X; gates -A7=MVAL -A8=MAL -A9=MAL -A10=MAL -A11=MAL -A12=MAL -A13=MAL -A14=MAL -A15=MAL -A16=MAL -A17=MAL -A18=MAL -A19=MAL -A20=MAL -A21=MAL -A22=MAL -A23=MAL -A24=MAL -A25=MAL -A26=MAL -B7=MVAL -B8=MAL -B9=MAL -B10=MAL -B11=MAL -B12=MAL -B13=MAL -B14=MAL -B15=MAL -B16=MAL -B17=MAL -B18=MAL -B19=MAL -B20=MAL -B21=MAL -B22=MAL -B23=MAL -B24=MAL -B25=MAL -B26=MAL -C7=MVAL -C8=MAL -C9=MAL -C10=MAL -C11=MAL -C12=MAL -C13=MAL -C14=MAL -C15=MAL -C16=MAL -C17=MAL -C18=MAL -C19=MAL -C20=MAL -C21=MAL -C22=MAL -C23=MAL -C24=MAL -C25=MAL -C26=MAL -1=COAX -2=COAX -3=COAX -4=COAX

## M60-4C  [M60-4C]
A1  -1:S1  pas
A3  -1:S2  pas
A4  -2:S1  pas
A6  -2:S2  pas
A7  -A7:S  pas
A8  -A8:S  pas
A9  -A9:S  pas
A10  -A10:S  pas
A11  -A11:S  pas
A12  -A12:S  pas
A13  -A13:S  pas
A14  -A14:S  pas
A15  -A15:S  pas
A16  -A16:S  pas
A17  -A17:S  pas
A18  -A18:S  pas
A19  -A19:S  pas
A20  -A20:S  pas
A21  -A21:S  pas
A22  -A22:S  pas
A23  -A23:S  pas
A24  -A24:S  pas
A25  -A25:S  pas
A26  -A26:S  pas
A27  -3:S1  pas
A29  -3:S2  pas
A30  -4:S1  pas
A32  -4:S2  pas
B2  -1:S  pas
B5  -2:S  pas
B7  -B7:S  pas
B8  -B8:S  pas
B9  -B9:S  pas
B10  -B10:S  pas
B11  -B11:S  pas
B12  -B12:S  pas
B13  -B13:S  pas
B14  -B14:S  pas
B15  -B15:S  pas
B16  -B16:S  pas
B17  -B17:S  pas
B18  -B18:S  pas
B19  -B19:S  pas
B20  -B20:S  pas
B21  -B21:S  pas
B22  -B22:S  pas
B23  -B23:S  pas
B24  -B24:S  pas
B25  -B25:S  pas
B26  -B26:S  pas
B28  -3:S  pas
B31  -4:S  pas
C1  -1:S3  pas
C3  -1:S4  pas
C4  -2:S3  pas
C6  -2:S4  pas
C7  -C7:S  pas
C8  -C8:S  pas
C9  -C9:S  pas
C10  -C10:S  pas
C11  -C11:S  pas
C12  -C12:S  pas
C13  -C13:S  pas
C14  -C14:S  pas
C15  -C15:S  pas
C16  -C16:S  pas
C17  -C17:S  pas
C18  -C18:S  pas
C19  -C19:S  pas
C20  -C20:S  pas
C21  -C21:S  pas
C22  -C22:S  pas
C23  -C23:S  pas
C24  -C24:S  pas
C25  -C25:S  pas
C26  -C26:S  pas
C27  -3:S3  pas
C29  -3:S4  pas
C30  -4:S3  pas
C32  -4:S4  pas

## Footprint M60-4C (pad centres in mm)
CONNECTOR male, 60 pins + 4 coax type C, rows ABC, grid 2.54 mm
drill 1.016 octagon: A1 -2.54,39.37; A3 -2.54,34.29; A4 -2.54,31.75; A6 -2.54,26.67; A7 -2.54,24.13; A8 -2.54,21.59; A9 -2.54,19.05; A10 -2.54,16.51; A11 -2.54,13.97; A12 -2.54,11.43; A13 -2.54,8.89; A14 -2.54,6.35; A15 -2.54,3.81; A16 -2.54,1.27; A17 -2.54,-1.27; A18 -2.54,-3.81; A19 -2.54,-6.35; A20 -2.54,-8.89; A21 -2.54,-11.43; A22 -2.54,-13.97; A23 -2.54,-16.51; A24 -2.54,-19.05; A25 -2.54,-21.59; A26 -2.54,-24.13; A27 -2.54,-26.67; A29 -2.54,-31.75; A30 -2.54,-34.29; A32 -2.54,-39.37; B2 -5.08,36.83; B5 -5.08,29.21; B7 -5.08,24.13; B8 -5.08,21.59; B9 -5.08,19.05; B10 -5.08,16.51; B11 -5.08,13.97; B12 -5.08,11.43; B13 -5.08,8.89; B14 -5.08,6.35; B15 -5.08,3.81; B16 -5.08,1.27; B17 -5.08,-1.27; B18 -5.08,-3.81; B19 -5.08,-6.35; B20 -5.08,-8.89; B21 -5.08,-11.43; B22 -5.08,-13.97; B23 -5.08,-16.51; B24 -5.08,-19.05; B25 -5.08,-21.59; B26 -5.08,-24.13; B28 -5.08,-29.21; B31 -5.08,-36.83; C1 -7.62,39.37; C3 -7.62,34.29; C4 -7.62,31.75; C6 -7.62,26.67; C7 -7.62,24.13; C8 -7.62,21.59; C9 -7.62,19.05; C10 -7.62,16.51; C11 -7.62,13.97; C12 -7.62,11.43; C13 -7.62,8.89; C14 -7.62,6.35; C15 -7.62,3.81; C16 -7.62,1.27; C17 -7.62,-1.27; C18 -7.62,-3.81; C19 -7.62,-6.35; C20 -7.62,-8.89; C21 -7.62,-11.43; C22 -7.62,-13.97; C23 -7.62,-16.51; C24 -7.62,-19.05; C25 -7.62,-21.59; C26 -7.62,-24.13; C27 -7.62,-26.67; C29 -7.62,-31.75; C30 -7.62,-34.29; C32 -7.62,-39.37
hole 2.794 at 0,44.45
hole 2.794 at 0,-44.45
